VERSION 5.7 ;
  NOWIREEXTENSIONATPIN ON ;
  DIVIDERCHAR "/" ;
  BUSBITCHARS "[]" ;
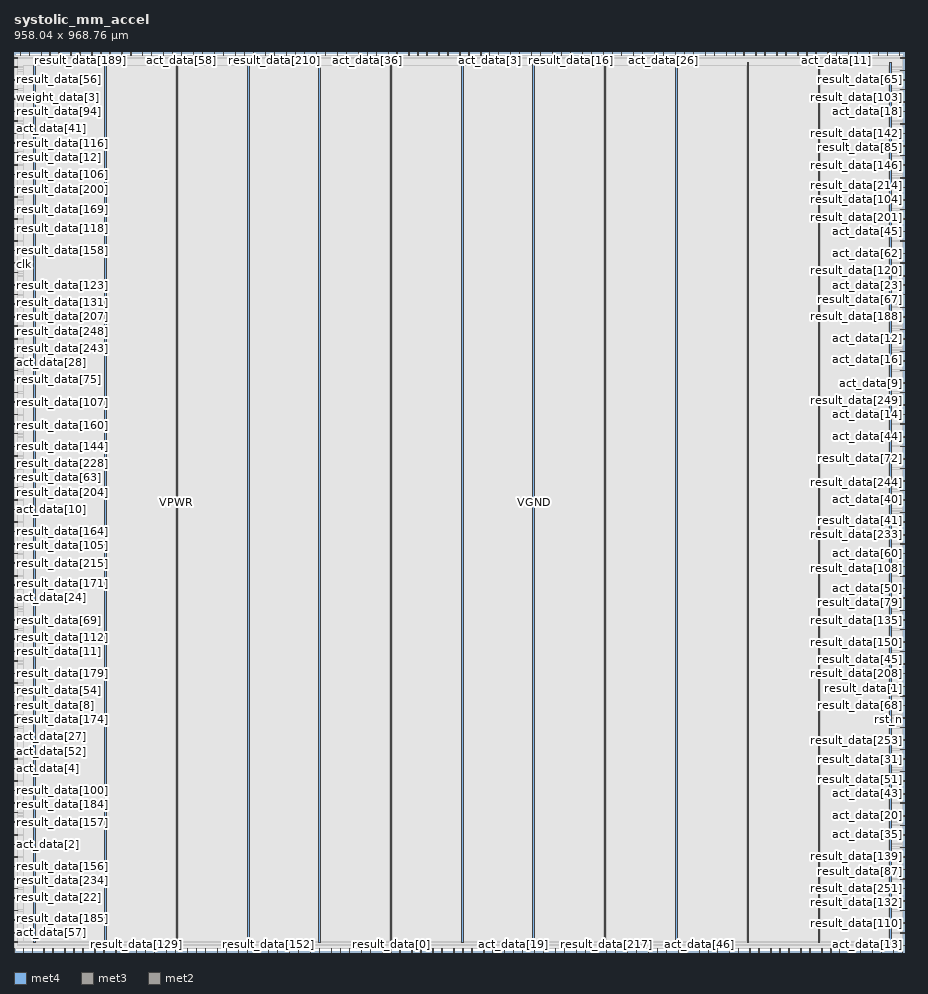
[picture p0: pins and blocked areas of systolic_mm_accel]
MACRO systolic_mm_accel
  CLASS BLOCK ;
  FOREIGN systolic_mm_accel ;
  ORIGIN 0.000 0.000 ;
  SIZE 958.040 BY 968.760 ;
  PIN VGND
    DIRECTION INOUT ;
    USE GROUND ;
    PORT
      LAYER met4 ;
        RECT 97.840 10.640 99.440 957.680 ;
    END
    PORT
      LAYER met4 ;
        RECT 251.440 10.640 253.040 957.680 ;
    END
    PORT
      LAYER met4 ;
        RECT 405.040 10.640 406.640 957.680 ;
    END
    PORT
      LAYER met4 ;
        RECT 558.640 10.640 560.240 957.680 ;
    END
    PORT
      LAYER met4 ;
        RECT 712.240 10.640 713.840 957.680 ;
    END
    PORT
      LAYER met4 ;
        RECT 865.840 10.640 867.440 957.680 ;
    END
  END VGND
  PIN VPWR
    DIRECTION INOUT ;
    USE POWER ;
    PORT
      LAYER met4 ;
        RECT 21.040 10.640 22.640 957.680 ;
    END
    PORT
      LAYER met4 ;
        RECT 174.640 10.640 176.240 957.680 ;
    END
    PORT
      LAYER met4 ;
        RECT 328.240 10.640 329.840 957.680 ;
    END
    PORT
      LAYER met4 ;
        RECT 481.840 10.640 483.440 957.680 ;
    END
    PORT
      LAYER met4 ;
        RECT 635.440 10.640 637.040 957.680 ;
    END
    PORT
      LAYER met4 ;
        RECT 789.040 10.640 790.640 957.680 ;
    END
    PORT
      LAYER met4 ;
        RECT 942.640 10.640 944.240 957.680 ;
    END
  END VPWR
  PIN act_data[0]
    DIRECTION INPUT ;
    USE SIGNAL ;
    ANTENNAGATEAREA 0.647700 ;
    ANTENNADIFFAREA 0.434700 ;
    PORT
      LAYER met3 ;
        RECT 0.000 499.840 4.000 500.440 ;
    END
  END act_data[0]
  PIN act_data[10]
    DIRECTION INPUT ;
    USE SIGNAL ;
    ANTENNAGATEAREA 0.647700 ;
    ANTENNADIFFAREA 0.434700 ;
    PORT
      LAYER met3 ;
        RECT 0.000 476.040 4.000 476.640 ;
    END
  END act_data[10]
  PIN act_data[11]
    DIRECTION INPUT ;
    USE SIGNAL ;
    ANTENNAGATEAREA 0.647700 ;
    ANTENNADIFFAREA 0.434700 ;
    PORT
      LAYER met2 ;
        RECT 885.590 964.760 885.870 968.760 ;
    END
  END act_data[11]
  PIN act_data[12]
    DIRECTION INPUT ;
    USE SIGNAL ;
    ANTENNAGATEAREA 0.593700 ;
    ANTENNADIFFAREA 0.434700 ;
    PORT
      LAYER met3 ;
        RECT 954.040 659.640 958.040 660.240 ;
    END
  END act_data[12]
  PIN act_data[13]
    DIRECTION INPUT ;
    USE SIGNAL ;
    ANTENNAGATEAREA 0.860700 ;
    ANTENNADIFFAREA 0.434700 ;
    PORT
      LAYER met2 ;
        RECT 924.230 0.000 924.510 4.000 ;
    END
  END act_data[13]
  PIN act_data[14]
    DIRECTION INPUT ;
    USE SIGNAL ;
    ANTENNAGATEAREA 0.593700 ;
    ANTENNADIFFAREA 0.434700 ;
    PORT
      LAYER met3 ;
        RECT 954.040 578.040 958.040 578.640 ;
    END
  END act_data[14]
  PIN act_data[15]
    DIRECTION INPUT ;
    USE SIGNAL ;
    ANTENNAGATEAREA 0.682200 ;
    ANTENNADIFFAREA 0.434700 ;
    PORT
      LAYER met2 ;
        RECT 769.670 0.000 769.950 4.000 ;
    END
  END act_data[15]
  PIN act_data[16]
    DIRECTION INPUT ;
    USE SIGNAL ;
    ANTENNAGATEAREA 0.593700 ;
    ANTENNADIFFAREA 0.434700 ;
    PORT
      LAYER met3 ;
        RECT 954.040 646.040 958.040 646.640 ;
    END
  END act_data[16]
  PIN act_data[17]
    DIRECTION INPUT ;
    USE SIGNAL ;
    ANTENNAGATEAREA 0.682200 ;
    ANTENNADIFFAREA 0.434700 ;
    PORT
      LAYER met2 ;
        RECT 296.330 0.000 296.610 4.000 ;
    END
  END act_data[17]
  PIN act_data[18]
    DIRECTION INPUT ;
    USE SIGNAL ;
    ANTENNAGATEAREA 0.647700 ;
    ANTENNADIFFAREA 0.434700 ;
    PORT
      LAYER met3 ;
        RECT 954.040 904.440 958.040 905.040 ;
    END
  END act_data[18]
  PIN act_data[19]
    DIRECTION INPUT ;
    USE SIGNAL ;
    ANTENNAGATEAREA 0.647700 ;
    ANTENNADIFFAREA 0.434700 ;
    PORT
      LAYER met2 ;
        RECT 537.830 0.000 538.110 4.000 ;
    END
  END act_data[19]
  PIN act_data[1]
    DIRECTION INPUT ;
    USE SIGNAL ;
    ANTENNAGATEAREA 0.682200 ;
    ANTENNADIFFAREA 0.434700 ;
    PORT
      LAYER met3 ;
        RECT 0.000 336.640 4.000 337.240 ;
    END
  END act_data[1]
  PIN act_data[20]
    DIRECTION INPUT ;
    USE SIGNAL ;
    ANTENNAGATEAREA 0.682200 ;
    ANTENNADIFFAREA 0.434700 ;
    PORT
      LAYER met3 ;
        RECT 954.040 146.240 958.040 146.840 ;
    END
  END act_data[20]
  PIN act_data[21]
    DIRECTION INPUT ;
    USE SIGNAL ;
    ANTENNAGATEAREA 0.682200 ;
    ANTENNADIFFAREA 0.434700 ;
    PORT
      LAYER met2 ;
        RECT 901.690 0.000 901.970 4.000 ;
    END
  END act_data[21]
  PIN act_data[22]
    DIRECTION INPUT ;
    USE SIGNAL ;
    ANTENNAGATEAREA 0.860700 ;
    ANTENNADIFFAREA 0.434700 ;
    PORT
      LAYER met2 ;
        RECT 16.190 964.760 16.470 968.760 ;
    END
  END act_data[22]
  PIN act_data[23]
    DIRECTION INPUT ;
    USE SIGNAL ;
    ANTENNAGATEAREA 0.647700 ;
    ANTENNADIFFAREA 0.434700 ;
    PORT
      LAYER met3 ;
        RECT 954.040 717.440 958.040 718.040 ;
    END
  END act_data[23]
  PIN act_data[24]
    DIRECTION INPUT ;
    USE SIGNAL ;
    ANTENNAGATEAREA 0.682200 ;
    ANTENNADIFFAREA 0.434700 ;
    PORT
      LAYER met3 ;
        RECT 0.000 380.840 4.000 381.440 ;
    END
  END act_data[24]
  PIN act_data[25]
    DIRECTION INPUT ;
    USE SIGNAL ;
    ANTENNAGATEAREA 0.682200 ;
    ANTENNADIFFAREA 0.434700 ;
    PORT
      LAYER met2 ;
        RECT 257.690 964.760 257.970 968.760 ;
    END
  END act_data[25]
  PIN act_data[26]
    DIRECTION INPUT ;
    USE SIGNAL ;
    ANTENNAGATEAREA 0.593700 ;
    ANTENNADIFFAREA 0.434700 ;
    PORT
      LAYER met2 ;
        RECT 698.830 964.760 699.110 968.760 ;
    END
  END act_data[26]
  PIN act_data[27]
    DIRECTION INPUT ;
    USE SIGNAL ;
    ANTENNAGATEAREA 0.682200 ;
    ANTENNADIFFAREA 0.434700 ;
    PORT
      LAYER met3 ;
        RECT 0.000 231.240 4.000 231.840 ;
    END
  END act_data[27]
  PIN act_data[28]
    DIRECTION INPUT ;
    USE SIGNAL ;
    ANTENNAGATEAREA 0.682200 ;
    ANTENNADIFFAREA 0.434700 ;
    PORT
      LAYER met3 ;
        RECT 0.000 625.640 4.000 626.240 ;
    END
  END act_data[28]
  PIN act_data[29]
    DIRECTION INPUT ;
    USE SIGNAL ;
    ANTENNAGATEAREA 0.647700 ;
    ANTENNADIFFAREA 0.434700 ;
    PORT
      LAYER met2 ;
        RECT 528.170 0.000 528.450 4.000 ;
    END
  END act_data[29]
  PIN act_data[2]
    DIRECTION INPUT ;
    USE SIGNAL ;
    ANTENNAGATEAREA 0.860700 ;
    ANTENNADIFFAREA 0.434700 ;
    PORT
      LAYER met3 ;
        RECT 0.000 115.640 4.000 116.240 ;
    END
  END act_data[2]
  PIN act_data[30]
    DIRECTION INPUT ;
    USE SIGNAL ;
    ANTENNAGATEAREA 0.682200 ;
    ANTENNADIFFAREA 0.434700 ;
    PORT
      LAYER met2 ;
        RECT 264.130 0.000 264.410 4.000 ;
    END
  END act_data[30]
  PIN act_data[31]
    DIRECTION INPUT ;
    USE SIGNAL ;
    ANTENNAGATEAREA 0.682200 ;
    ANTENNADIFFAREA 0.434700 ;
    PORT
      LAYER met2 ;
        RECT 193.290 964.760 193.570 968.760 ;
    END
  END act_data[31]
  PIN act_data[32]
    DIRECTION INPUT ;
    USE SIGNAL ;
    ANTENNAGATEAREA 0.593700 ;
    ANTENNADIFFAREA 0.434700 ;
    PORT
      LAYER met2 ;
        RECT 869.490 0.000 869.770 4.000 ;
    END
  END act_data[32]
  PIN act_data[33]
    DIRECTION INPUT ;
    USE SIGNAL ;
    ANTENNAGATEAREA 0.682200 ;
    ANTENNADIFFAREA 0.434700 ;
    PORT
      LAYER met3 ;
        RECT 0.000 278.840 4.000 279.440 ;
    END
  END act_data[33]
  PIN act_data[34]
    DIRECTION INPUT ;
    USE SIGNAL ;
    ANTENNAGATEAREA 0.682200 ;
    ANTENNADIFFAREA 0.434700 ;
    PORT
      LAYER met3 ;
        RECT 0.000 639.240 4.000 639.840 ;
    END
  END act_data[34]
  PIN act_data[35]
    DIRECTION INPUT ;
    USE SIGNAL ;
    ANTENNAGATEAREA 0.647700 ;
    ANTENNADIFFAREA 0.434700 ;
    PORT
      LAYER met3 ;
        RECT 954.040 125.840 958.040 126.440 ;
    END
  END act_data[35]
  PIN act_data[36]
    DIRECTION INPUT ;
    USE SIGNAL ;
    ANTENNAGATEAREA 0.682200 ;
    ANTENNADIFFAREA 0.434700 ;
    PORT
      LAYER met2 ;
        RECT 380.050 964.760 380.330 968.760 ;
    END
  END act_data[36]
  PIN act_data[37]
    DIRECTION INPUT ;
    USE SIGNAL ;
    ANTENNAGATEAREA 0.860700 ;
    ANTENNADIFFAREA 0.434700 ;
    PORT
      LAYER met2 ;
        RECT 215.830 964.760 216.110 968.760 ;
    END
  END act_data[37]
  PIN act_data[38]
    DIRECTION INPUT ;
    USE SIGNAL ;
    ANTENNAGATEAREA 0.647700 ;
    ANTENNADIFFAREA 0.434700 ;
    PORT
      LAYER met3 ;
        RECT 954.040 112.240 958.040 112.840 ;
    END
  END act_data[38]
  PIN act_data[39]
    DIRECTION INPUT ;
    USE SIGNAL ;
    ANTENNAGATEAREA 0.682200 ;
    ANTENNADIFFAREA 0.434700 ;
    PORT
      LAYER met2 ;
        RECT 334.970 964.760 335.250 968.760 ;
    END
  END act_data[39]
  PIN act_data[3]
    DIRECTION INPUT ;
    USE SIGNAL ;
    ANTENNAGATEAREA 0.593700 ;
    ANTENNADIFFAREA 0.434700 ;
    PORT
      LAYER met2 ;
        RECT 512.070 964.760 512.350 968.760 ;
    END
  END act_data[3]
  PIN act_data[40]
    DIRECTION INPUT ;
    USE SIGNAL ;
    ANTENNAGATEAREA 0.631200 ;
    ANTENNADIFFAREA 0.434700 ;
    PORT
      LAYER met3 ;
        RECT 954.040 486.240 958.040 486.840 ;
    END
  END act_data[40]
  PIN act_data[41]
    DIRECTION INPUT ;
    USE SIGNAL ;
    ANTENNAGATEAREA 0.860700 ;
    ANTENNADIFFAREA 0.434700 ;
    PORT
      LAYER met3 ;
        RECT 0.000 894.240 4.000 894.840 ;
    END
  END act_data[41]
  PIN act_data[42]
    DIRECTION INPUT ;
    USE SIGNAL ;
    ANTENNAGATEAREA 0.860700 ;
    ANTENNADIFFAREA 0.434700 ;
    PORT
      LAYER met2 ;
        RECT 54.830 0.000 55.110 4.000 ;
    END
  END act_data[42]
  PIN act_data[43]
    DIRECTION INPUT ;
    USE SIGNAL ;
    ANTENNAGATEAREA 0.560700 ;
    ANTENNADIFFAREA 0.434700 ;
    PORT
      LAYER met3 ;
        RECT 954.040 170.040 958.040 170.640 ;
    END
  END act_data[43]
  PIN act_data[44]
    DIRECTION INPUT ;
    USE SIGNAL ;
    ANTENNAGATEAREA 0.631200 ;
    ANTENNADIFFAREA 0.434700 ;
    PORT
      LAYER met3 ;
        RECT 954.040 554.240 958.040 554.840 ;
    END
  END act_data[44]
  PIN act_data[45]
    DIRECTION INPUT ;
    USE SIGNAL ;
    ANTENNAGATEAREA 0.647700 ;
    ANTENNADIFFAREA 0.434700 ;
    PORT
      LAYER met3 ;
        RECT 954.040 775.240 958.040 775.840 ;
    END
  END act_data[45]
  PIN act_data[46]
    DIRECTION INPUT ;
    USE SIGNAL ;
    ANTENNAGATEAREA 0.593700 ;
    ANTENNADIFFAREA 0.434700 ;
    PORT
      LAYER met2 ;
        RECT 737.470 0.000 737.750 4.000 ;
    END
  END act_data[46]
  PIN act_data[47]
    DIRECTION INPUT ;
    USE SIGNAL ;
    ANTENNAGATEAREA 0.647700 ;
    ANTENNADIFFAREA 0.434700 ;
    PORT
      LAYER met2 ;
        RECT 660.190 0.000 660.470 4.000 ;
    END
  END act_data[47]
  PIN act_data[48]
    DIRECTION INPUT ;
    USE SIGNAL ;
    ANTENNAGATEAREA 0.631200 ;
    ANTENNADIFFAREA 0.434700 ;
    PORT
      LAYER met2 ;
        RECT 875.930 964.760 876.210 968.760 ;
    END
  END act_data[48]
  PIN act_data[49]
    DIRECTION INPUT ;
    USE SIGNAL ;
    ANTENNAGATEAREA 0.560700 ;
    ANTENNADIFFAREA 0.434700 ;
    PORT
      LAYER met3 ;
        RECT 954.040 251.640 958.040 252.240 ;
    END
  END act_data[49]
  PIN act_data[4]
    DIRECTION INPUT ;
    USE SIGNAL ;
    ANTENNAGATEAREA 0.929700 ;
    ANTENNADIFFAREA 0.434700 ;
    PORT
      LAYER met3 ;
        RECT 0.000 197.240 4.000 197.840 ;
    END
  END act_data[4]
  PIN act_data[50]
    DIRECTION INPUT ;
    USE SIGNAL ;
    ANTENNAGATEAREA 0.631200 ;
    ANTENNADIFFAREA 0.434700 ;
    PORT
      LAYER met3 ;
        RECT 954.040 391.040 958.040 391.640 ;
    END
  END act_data[50]
  PIN act_data[51]
    DIRECTION INPUT ;
    USE SIGNAL ;
    ANTENNAGATEAREA 0.631200 ;
    ANTENNADIFFAREA 0.434700 ;
    PORT
      LAYER met2 ;
        RECT 930.670 964.760 930.950 968.760 ;
    END
  END act_data[51]
  PIN act_data[52]
    DIRECTION INPUT ;
    USE SIGNAL ;
    ANTENNAGATEAREA 0.860700 ;
    ANTENNADIFFAREA 0.434700 ;
    PORT
      LAYER met3 ;
        RECT 0.000 207.440 4.000 208.040 ;
    END
  END act_data[52]
  PIN act_data[53]
    DIRECTION INPUT ;
    USE SIGNAL ;
    ANTENNAGATEAREA 0.593700 ;
    ANTENNADIFFAREA 0.434700 ;
    PORT
      LAYER met2 ;
        RECT 544.270 964.760 544.550 968.760 ;
    END
  END act_data[53]
  PIN act_data[54]
    DIRECTION INPUT ;
    USE SIGNAL ;
    ANTENNAGATEAREA 0.631200 ;
    ANTENNADIFFAREA 0.434700 ;
    PORT
      LAYER met2 ;
        RECT 853.390 964.760 853.670 968.760 ;
    END
  END act_data[54]
  PIN act_data[55]
    DIRECTION INPUT ;
    USE SIGNAL ;
    ANTENNAGATEAREA 0.560700 ;
    ANTENNADIFFAREA 0.434700 ;
    PORT
      LAYER met2 ;
        RECT 676.290 964.760 676.570 968.760 ;
    END
  END act_data[55]
  PIN act_data[56]
    DIRECTION INPUT ;
    USE SIGNAL ;
    ANTENNAGATEAREA 0.647700 ;
    ANTENNADIFFAREA 0.434700 ;
    PORT
      LAYER met2 ;
        RECT 138.550 964.760 138.830 968.760 ;
    END
  END act_data[56]
  PIN act_data[57]
    DIRECTION INPUT ;
    USE SIGNAL ;
    ANTENNAGATEAREA 0.929700 ;
    ANTENNADIFFAREA 0.434700 ;
    PORT
      LAYER met3 ;
        RECT 0.000 20.440 4.000 21.040 ;
    END
  END act_data[57]
  PIN act_data[58]
    DIRECTION INPUT ;
    USE SIGNAL ;
    ANTENNAGATEAREA 0.647700 ;
    ANTENNADIFFAREA 0.434700 ;
    PORT
      LAYER met2 ;
        RECT 180.410 964.760 180.690 968.760 ;
    END
  END act_data[58]
  PIN act_data[59]
    DIRECTION INPUT ;
    USE SIGNAL ;
    ANTENNAGATEAREA 0.647700 ;
    ANTENNADIFFAREA 0.434700 ;
    PORT
      LAYER met2 ;
        RECT 93.470 964.760 93.750 968.760 ;
    END
  END act_data[59]
  PIN act_data[5]
    DIRECTION INPUT ;
    USE SIGNAL ;
    ANTENNAGATEAREA 0.647700 ;
    ANTENNADIFFAREA 0.434700 ;
    PORT
      LAYER met2 ;
        RECT 653.750 964.760 654.030 968.760 ;
    END
  END act_data[5]
  PIN act_data[60]
    DIRECTION INPUT ;
    USE SIGNAL ;
    ANTENNAGATEAREA 0.631200 ;
    ANTENNADIFFAREA 0.434700 ;
    PORT
      LAYER met3 ;
        RECT 954.040 428.440 958.040 429.040 ;
    END
  END act_data[60]
  PIN act_data[61]
    DIRECTION INPUT ;
    USE SIGNAL ;
    ANTENNAGATEAREA 0.647700 ;
    ANTENNADIFFAREA 0.434700 ;
    PORT
      LAYER met2 ;
        RECT 438.010 0.000 438.290 4.000 ;
    END
  END act_data[61]
  PIN act_data[62]
    DIRECTION INPUT ;
    USE SIGNAL ;
    ANTENNAGATEAREA 0.631200 ;
    ANTENNADIFFAREA 0.434700 ;
    PORT
      LAYER met3 ;
        RECT 954.040 751.440 958.040 752.040 ;
    END
  END act_data[62]
  PIN act_data[63]
    DIRECTION INPUT ;
    USE SIGNAL ;
    ANTENNAGATEAREA 0.860700 ;
    ANTENNADIFFAREA 0.434700 ;
    PORT
      LAYER met2 ;
        RECT 151.430 0.000 151.710 4.000 ;
    END
  END act_data[63]
  PIN act_data[6]
    DIRECTION INPUT ;
    USE SIGNAL ;
    ANTENNAGATEAREA 0.647700 ;
    ANTENNADIFFAREA 0.434700 ;
    PORT
      LAYER met2 ;
        RECT 898.470 964.760 898.750 968.760 ;
    END
  END act_data[6]
  PIN act_data[7]
    DIRECTION INPUT ;
    USE SIGNAL ;
    ANTENNAGATEAREA 1.177200 ;
    ANTENNADIFFAREA 0.434700 ;
    PORT
      LAYER met3 ;
        RECT 0.000 10.240 4.000 10.840 ;
    END
  END act_data[7]
  PIN act_data[8]
    DIRECTION INPUT ;
    USE SIGNAL ;
    ANTENNAGATEAREA 0.647700 ;
    ANTENNADIFFAREA 0.434700 ;
    PORT
      LAYER met2 ;
        RECT 557.150 964.760 557.430 968.760 ;
    END
  END act_data[8]
  PIN act_data[9]
    DIRECTION INPUT ;
    USE SIGNAL ;
    ANTENNAGATEAREA 0.593700 ;
    ANTENNADIFFAREA 0.434700 ;
    PORT
      LAYER met3 ;
        RECT 954.040 612.040 958.040 612.640 ;
    END
  END act_data[9]
  PIN act_ready
    DIRECTION OUTPUT TRISTATE ;
    USE SIGNAL ;
    ANTENNADIFFAREA 0.795200 ;
    PORT
      LAYER met2 ;
        RECT 225.490 964.760 225.770 968.760 ;
    END
  END act_ready
  PIN act_valid
    DIRECTION INPUT ;
    USE SIGNAL ;
    ANTENNAGATEAREA 0.647700 ;
    ANTENNADIFFAREA 0.434700 ;
    PORT
      LAYER met2 ;
        RECT 621.550 964.760 621.830 968.760 ;
    END
  END act_valid
  PIN clk
    DIRECTION INPUT ;
    USE SIGNAL ;
    ANTENNAGATEAREA 1.286700 ;
    ANTENNADIFFAREA 0.434700 ;
    PORT
      LAYER met3 ;
        RECT 0.000 731.040 4.000 731.640 ;
    END
  END clk
  PIN result_data[0]
    DIRECTION OUTPUT TRISTATE ;
    USE SIGNAL ;
    ANTENNADIFFAREA 0.795200 ;
    PORT
      LAYER met2 ;
        RECT 405.810 0.000 406.090 4.000 ;
    END
  END result_data[0]
  PIN result_data[100]
    DIRECTION OUTPUT TRISTATE ;
    USE SIGNAL ;
    ANTENNADIFFAREA 0.795200 ;
    PORT
      LAYER met3 ;
        RECT 0.000 173.440 4.000 174.040 ;
    END
  END result_data[100]
  PIN result_data[101]
    DIRECTION OUTPUT TRISTATE ;
    USE SIGNAL ;
    ANTENNADIFFAREA 0.445500 ;
    PORT
      LAYER met3 ;
        RECT 954.040 635.840 958.040 636.440 ;
    END
  END result_data[101]
  PIN result_data[102]
    DIRECTION OUTPUT TRISTATE ;
    USE SIGNAL ;
    ANTENNADIFFAREA 0.795200 ;
    PORT
      LAYER met2 ;
        RECT 241.590 0.000 241.870 4.000 ;
    END
  END result_data[102]
  PIN result_data[103]
    DIRECTION OUTPUT TRISTATE ;
    USE SIGNAL ;
    ANTENNADIFFAREA 0.445500 ;
    PORT
      LAYER met3 ;
        RECT 954.040 928.240 958.040 928.840 ;
    END
  END result_data[103]
  PIN result_data[104]
    DIRECTION OUTPUT TRISTATE ;
    USE SIGNAL ;
    ANTENNADIFFAREA 0.445500 ;
    PORT
      LAYER met3 ;
        RECT 954.040 809.240 958.040 809.840 ;
    END
  END result_data[104]
  PIN result_data[105]
    DIRECTION OUTPUT TRISTATE ;
    USE SIGNAL ;
    ANTENNADIFFAREA 0.795200 ;
    PORT
      LAYER met3 ;
        RECT 0.000 428.440 4.000 429.040 ;
    END
  END result_data[105]
  PIN result_data[106]
    DIRECTION OUTPUT TRISTATE ;
    USE SIGNAL ;
    ANTENNADIFFAREA 0.795200 ;
    PORT
      LAYER met3 ;
        RECT 0.000 836.440 4.000 837.040 ;
    END
  END result_data[106]
  PIN result_data[107]
    DIRECTION OUTPUT TRISTATE ;
    USE SIGNAL ;
    ANTENNADIFFAREA 0.795200 ;
    PORT
      LAYER met3 ;
        RECT 0.000 591.640 4.000 592.240 ;
    END
  END result_data[107]
  PIN result_data[108]
    DIRECTION OUTPUT TRISTATE ;
    USE SIGNAL ;
    ANTENNADIFFAREA 0.445500 ;
    PORT
      LAYER met3 ;
        RECT 954.040 404.640 958.040 405.240 ;
    END
  END result_data[108]
  PIN result_data[109]
    DIRECTION OUTPUT TRISTATE ;
    USE SIGNAL ;
    ANTENNADIFFAREA 0.795200 ;
    PORT
      LAYER met2 ;
        RECT 592.570 0.000 592.850 4.000 ;
    END
  END result_data[109]
  PIN result_data[10]
    DIRECTION OUTPUT TRISTATE ;
    USE SIGNAL ;
    ANTENNADIFFAREA 0.795200 ;
    PORT
      LAYER met2 ;
        RECT 186.850 0.000 187.130 4.000 ;
    END
  END result_data[10]
  PIN result_data[110]
    DIRECTION OUTPUT TRISTATE ;
    USE SIGNAL ;
    ANTENNADIFFAREA 0.445500 ;
    PORT
      LAYER met3 ;
        RECT 954.040 30.640 958.040 31.240 ;
    END
  END result_data[110]
  PIN result_data[111]
    DIRECTION OUTPUT TRISTATE ;
    USE SIGNAL ;
    ANTENNADIFFAREA 0.445500 ;
    PORT
      LAYER met3 ;
        RECT 954.040 159.840 958.040 160.440 ;
    END
  END result_data[111]
  PIN result_data[112]
    DIRECTION OUTPUT TRISTATE ;
    USE SIGNAL ;
    ANTENNADIFFAREA 0.795200 ;
    PORT
      LAYER met3 ;
        RECT 0.000 346.840 4.000 347.440 ;
    END
  END result_data[112]
  PIN result_data[113]
    DIRECTION OUTPUT TRISTATE ;
    USE SIGNAL ;
    ANTENNADIFFAREA 0.795200 ;
    PORT
      LAYER met2 ;
        RECT 460.550 0.000 460.830 4.000 ;
    END
  END result_data[113]
  PIN result_data[114]
    DIRECTION OUTPUT TRISTATE ;
    USE SIGNAL ;
    ANTENNADIFFAREA 0.795200 ;
    PORT
      LAYER met2 ;
        RECT 785.770 964.760 786.050 968.760 ;
    END
  END result_data[114]
  PIN result_data[115]
    DIRECTION OUTPUT TRISTATE ;
    USE SIGNAL ;
    ANTENNADIFFAREA 0.795200 ;
    PORT
      LAYER met3 ;
        RECT 954.040 20.440 958.040 21.040 ;
    END
  END result_data[115]
  PIN result_data[116]
    DIRECTION OUTPUT TRISTATE ;
    USE SIGNAL ;
    ANTENNADIFFAREA 0.795200 ;
    PORT
      LAYER met3 ;
        RECT 0.000 870.440 4.000 871.040 ;
    END
  END result_data[116]
  PIN result_data[117]
    DIRECTION OUTPUT TRISTATE ;
    USE SIGNAL ;
    ANTENNADIFFAREA 0.795200 ;
    PORT
      LAYER met2 ;
        RECT 753.570 964.760 753.850 968.760 ;
    END
  END result_data[117]
  PIN result_data[118]
    DIRECTION OUTPUT TRISTATE ;
    USE SIGNAL ;
    ANTENNADIFFAREA 0.795200 ;
    PORT
      LAYER met3 ;
        RECT 0.000 778.640 4.000 779.240 ;
    END
  END result_data[118]
  PIN result_data[119]
    DIRECTION OUTPUT TRISTATE ;
    USE SIGNAL ;
    ANTENNADIFFAREA 0.795200 ;
    PORT
      LAYER met2 ;
        RECT 953.210 964.760 953.490 968.760 ;
    END
  END result_data[119]
  PIN result_data[11]
    DIRECTION OUTPUT TRISTATE ;
    USE SIGNAL ;
    ANTENNADIFFAREA 0.795200 ;
    PORT
      LAYER met3 ;
        RECT 0.000 323.040 4.000 323.640 ;
    END
  END result_data[11]
  PIN result_data[120]
    DIRECTION OUTPUT TRISTATE ;
    USE SIGNAL ;
    ANTENNADIFFAREA 0.445500 ;
    PORT
      LAYER met3 ;
        RECT 954.040 741.240 958.040 741.840 ;
    END
  END result_data[120]
  PIN result_data[121]
    DIRECTION OUTPUT TRISTATE ;
    USE SIGNAL ;
    ANTENNADIFFAREA 0.795200 ;
    PORT
      LAYER met2 ;
        RECT 302.770 964.760 303.050 968.760 ;
    END
  END result_data[121]
  PIN result_data[122]
    DIRECTION OUTPUT TRISTATE ;
    USE SIGNAL ;
    ANTENNADIFFAREA 0.795200 ;
    PORT
      LAYER met2 ;
        RECT 830.850 964.760 831.130 968.760 ;
    END
  END result_data[122]
  PIN result_data[123]
    DIRECTION OUTPUT TRISTATE ;
    USE SIGNAL ;
    ANTENNADIFFAREA 0.795200 ;
    PORT
      LAYER met3 ;
        RECT 0.000 717.440 4.000 718.040 ;
    END
  END result_data[123]
  PIN result_data[124]
    DIRECTION OUTPUT TRISTATE ;
    USE SIGNAL ;
    ANTENNADIFFAREA 0.795200 ;
    PORT
      LAYER met2 ;
        RECT 370.390 964.760 370.670 968.760 ;
    END
  END result_data[124]
  PIN result_data[125]
    DIRECTION OUTPUT TRISTATE ;
    USE SIGNAL ;
    ANTENNADIFFAREA 0.795200 ;
    PORT
      LAYER met2 ;
        RECT 38.730 964.760 39.010 968.760 ;
    END
  END result_data[125]
  PIN result_data[126]
    DIRECTION OUTPUT TRISTATE ;
    USE SIGNAL ;
    ANTENNADIFFAREA 0.795200 ;
    PORT
      LAYER met2 ;
        RECT 328.530 0.000 328.810 4.000 ;
    END
  END result_data[126]
  PIN result_data[127]
    DIRECTION OUTPUT TRISTATE ;
    USE SIGNAL ;
    ANTENNADIFFAREA 0.795200 ;
    PORT
      LAYER met2 ;
        RECT 579.690 964.760 579.970 968.760 ;
    END
  END result_data[127]
  PIN result_data[128]
    DIRECTION OUTPUT TRISTATE ;
    USE SIGNAL ;
    ANTENNADIFFAREA 0.445500 ;
    PORT
      LAYER met2 ;
        RECT 161.090 964.760 161.370 968.760 ;
    END
  END result_data[128]
  PIN result_data[129]
    DIRECTION OUTPUT TRISTATE ;
    USE SIGNAL ;
    ANTENNADIFFAREA 0.795200 ;
    PORT
      LAYER met2 ;
        RECT 132.110 0.000 132.390 4.000 ;
    END
  END result_data[129]
  PIN result_data[12]
    DIRECTION OUTPUT TRISTATE ;
    USE SIGNAL ;
    ANTENNADIFFAREA 0.795200 ;
    PORT
      LAYER met3 ;
        RECT 0.000 846.640 4.000 847.240 ;
    END
  END result_data[12]
  PIN result_data[130]
    DIRECTION OUTPUT TRISTATE ;
    USE SIGNAL ;
    ANTENNADIFFAREA 0.795200 ;
    PORT
      LAYER met3 ;
        RECT 0.000 952.040 4.000 952.640 ;
    END
  END result_data[130]
  PIN result_data[131]
    DIRECTION OUTPUT TRISTATE ;
    USE SIGNAL ;
    ANTENNADIFFAREA 0.795200 ;
    PORT
      LAYER met3 ;
        RECT 0.000 707.240 4.000 707.840 ;
    END
  END result_data[131]
  PIN result_data[132]
    DIRECTION OUTPUT TRISTATE ;
    USE SIGNAL ;
    ANTENNADIFFAREA 0.445500 ;
    PORT
      LAYER met3 ;
        RECT 954.040 44.240 958.040 44.840 ;
    END
  END result_data[132]
  PIN result_data[133]
    DIRECTION OUTPUT TRISTATE ;
    USE SIGNAL ;
    ANTENNADIFFAREA 0.445500 ;
    PORT
      LAYER met2 ;
        RECT 148.210 964.760 148.490 968.760 ;
    END
  END result_data[133]
  PIN result_data[134]
    DIRECTION OUTPUT TRISTATE ;
    USE SIGNAL ;
    ANTENNADIFFAREA 0.445500 ;
    PORT
      LAYER met2 ;
        RECT 347.850 964.760 348.130 968.760 ;
    END
  END result_data[134]
  PIN result_data[135]
    DIRECTION OUTPUT TRISTATE ;
    USE SIGNAL ;
    ANTENNADIFFAREA 0.445500 ;
    PORT
      LAYER met3 ;
        RECT 954.040 357.040 958.040 357.640 ;
    END
  END result_data[135]
  PIN result_data[136]
    DIRECTION OUTPUT TRISTATE ;
    USE SIGNAL ;
    ANTENNADIFFAREA 0.795200 ;
    PORT
      LAYER met2 ;
        RECT 251.250 0.000 251.530 4.000 ;
    END
  END result_data[136]
  PIN result_data[137]
    DIRECTION OUTPUT TRISTATE ;
    USE SIGNAL ;
    ANTENNADIFFAREA 0.795200 ;
    PORT
      LAYER met2 ;
        RECT 956.430 0.000 956.710 4.000 ;
    END
  END result_data[137]
  PIN result_data[138]
    DIRECTION OUTPUT TRISTATE ;
    USE SIGNAL ;
    ANTENNADIFFAREA 0.795200 ;
    PORT
      LAYER met2 ;
        RECT 547.490 0.000 547.770 4.000 ;
    END
  END result_data[138]
  PIN result_data[139]
    DIRECTION OUTPUT TRISTATE ;
    USE SIGNAL ;
    ANTENNADIFFAREA 0.795200 ;
    PORT
      LAYER met3 ;
        RECT 954.040 102.040 958.040 102.640 ;
    END
  END result_data[139]
  PIN result_data[13]
    DIRECTION OUTPUT TRISTATE ;
    USE SIGNAL ;
    ANTENNADIFFAREA 0.795200 ;
    PORT
      LAYER met2 ;
        RECT 921.010 964.760 921.290 968.760 ;
    END
  END result_data[13]
  PIN result_data[140]
    DIRECTION OUTPUT TRISTATE ;
    USE SIGNAL ;
    ANTENNADIFFAREA 0.795200 ;
    PORT
      LAYER met2 ;
        RECT 779.330 0.000 779.610 4.000 ;
    END
  END result_data[140]
  PIN result_data[141]
    DIRECTION OUTPUT TRISTATE ;
    USE SIGNAL ;
    ANTENNADIFFAREA 0.795200 ;
    PORT
      LAYER met2 ;
        RECT 360.730 0.000 361.010 4.000 ;
    END
  END result_data[141]
  PIN result_data[142]
    DIRECTION OUTPUT TRISTATE ;
    USE SIGNAL ;
    ANTENNADIFFAREA 0.445500 ;
    PORT
      LAYER met3 ;
        RECT 954.040 880.640 958.040 881.240 ;
    END
  END result_data[142]
  PIN result_data[143]
    DIRECTION OUTPUT TRISTATE ;
    USE SIGNAL ;
    ANTENNADIFFAREA 0.795200 ;
    PORT
      LAYER met2 ;
        RECT 238.370 964.760 238.650 968.760 ;
    END
  END result_data[143]
  PIN result_data[144]
    DIRECTION OUTPUT TRISTATE ;
    USE SIGNAL ;
    ANTENNADIFFAREA 0.795200 ;
    PORT
      LAYER met3 ;
        RECT 0.000 544.040 4.000 544.640 ;
    END
  END result_data[144]
  PIN result_data[145]
    DIRECTION OUTPUT TRISTATE ;
    USE SIGNAL ;
    ANTENNADIFFAREA 0.445500 ;
    PORT
      LAYER met3 ;
        RECT 954.040 183.640 958.040 184.240 ;
    END
  END result_data[145]
  PIN result_data[146]
    DIRECTION OUTPUT TRISTATE ;
    USE SIGNAL ;
    ANTENNADIFFAREA 0.445500 ;
    PORT
      LAYER met3 ;
        RECT 954.040 846.640 958.040 847.240 ;
    END
  END result_data[146]
  PIN result_data[147]
    DIRECTION OUTPUT TRISTATE ;
    USE SIGNAL ;
    ANTENNADIFFAREA 0.795200 ;
    PORT
      LAYER met2 ;
        RECT 911.350 0.000 911.630 4.000 ;
    END
  END result_data[147]
  PIN result_data[148]
    DIRECTION OUTPUT TRISTATE ;
    USE SIGNAL ;
    ANTENNADIFFAREA 0.795200 ;
    PORT
      LAYER met2 ;
        RECT 383.270 0.000 383.550 4.000 ;
    END
  END result_data[148]
  PIN result_data[149]
    DIRECTION OUTPUT TRISTATE ;
    USE SIGNAL ;
    ANTENNADIFFAREA 0.795200 ;
    PORT
      LAYER met2 ;
        RECT 801.870 0.000 802.150 4.000 ;
    END
  END result_data[149]
  PIN result_data[14]
    DIRECTION OUTPUT TRISTATE ;
    USE SIGNAL ;
    ANTENNADIFFAREA 0.795200 ;
    PORT
      LAYER met2 ;
        RECT 96.690 0.000 96.970 4.000 ;
    END
  END result_data[14]
  PIN result_data[150]
    DIRECTION OUTPUT TRISTATE ;
    USE SIGNAL ;
    ANTENNADIFFAREA 0.445500 ;
    PORT
      LAYER met3 ;
        RECT 954.040 333.240 958.040 333.840 ;
    END
  END result_data[150]
  PIN result_data[151]
    DIRECTION OUTPUT TRISTATE ;
    USE SIGNAL ;
    ANTENNADIFFAREA 0.445500 ;
    PORT
      LAYER met3 ;
        RECT 954.040 625.640 958.040 626.240 ;
    END
  END result_data[151]
  PIN result_data[152]
    DIRECTION OUTPUT TRISTATE ;
    USE SIGNAL ;
    ANTENNADIFFAREA 0.795200 ;
    PORT
      LAYER met2 ;
        RECT 273.790 0.000 274.070 4.000 ;
    END
  END result_data[152]
  PIN result_data[153]
    DIRECTION OUTPUT TRISTATE ;
    USE SIGNAL ;
    ANTENNADIFFAREA 0.795200 ;
    PORT
      LAYER met3 ;
        RECT 954.040 88.440 958.040 89.040 ;
    END
  END result_data[153]
  PIN result_data[154]
    DIRECTION OUTPUT TRISTATE ;
    USE SIGNAL ;
    ANTENNADIFFAREA 0.795200 ;
    PORT
      LAYER met2 ;
        RECT 756.790 0.000 757.070 4.000 ;
    END
  END result_data[154]
  PIN result_data[155]
    DIRECTION OUTPUT TRISTATE ;
    USE SIGNAL ;
    ANTENNADIFFAREA 0.795200 ;
    PORT
      LAYER met2 ;
        RECT 570.030 0.000 570.310 4.000 ;
    END
  END result_data[155]
  PIN result_data[156]
    DIRECTION OUTPUT TRISTATE ;
    USE SIGNAL ;
    ANTENNADIFFAREA 0.795200 ;
    PORT
      LAYER met3 ;
        RECT 0.000 91.840 4.000 92.440 ;
    END
  END result_data[156]
  PIN result_data[157]
    DIRECTION OUTPUT TRISTATE ;
    USE SIGNAL ;
    ANTENNADIFFAREA 0.795200 ;
    PORT
      LAYER met3 ;
        RECT 0.000 139.440 4.000 140.040 ;
    END
  END result_data[157]
  PIN result_data[158]
    DIRECTION OUTPUT TRISTATE ;
    USE SIGNAL ;
    ANTENNADIFFAREA 0.795200 ;
    PORT
      LAYER met3 ;
        RECT 0.000 754.840 4.000 755.440 ;
    END
  END result_data[158]
  PIN result_data[159]
    DIRECTION OUTPUT TRISTATE ;
    USE SIGNAL ;
    ANTENNADIFFAREA 0.445500 ;
    PORT
      LAYER met3 ;
        RECT 954.040 380.840 958.040 381.440 ;
    END
  END result_data[159]
  PIN result_data[15]
    DIRECTION OUTPUT TRISTATE ;
    USE SIGNAL ;
    ANTENNADIFFAREA 0.795200 ;
    PORT
      LAYER met2 ;
        RECT 248.030 964.760 248.310 968.760 ;
    END
  END result_data[15]
  PIN result_data[160]
    DIRECTION OUTPUT TRISTATE ;
    USE SIGNAL ;
    ANTENNADIFFAREA 0.795200 ;
    PORT
      LAYER met3 ;
        RECT 0.000 557.640 4.000 558.240 ;
    END
  END result_data[160]
  PIN result_data[161]
    DIRECTION OUTPUT TRISTATE ;
    USE SIGNAL ;
    ANTENNADIFFAREA 0.445500 ;
    PORT
      LAYER met3 ;
        RECT 954.040 867.040 958.040 867.640 ;
    END
  END result_data[161]
  PIN result_data[162]
    DIRECTION OUTPUT TRISTATE ;
    USE SIGNAL ;
    ANTENNADIFFAREA 0.795200 ;
    PORT
      LAYER met2 ;
        RECT 473.430 0.000 473.710 4.000 ;
    END
  END result_data[162]
  PIN result_data[163]
    DIRECTION OUTPUT TRISTATE ;
    USE SIGNAL ;
    ANTENNADIFFAREA 0.795200 ;
    PORT
      LAYER met2 ;
        RECT 61.270 964.760 61.550 968.760 ;
    END
  END result_data[163]
  PIN result_data[164]
    DIRECTION OUTPUT TRISTATE ;
    USE SIGNAL ;
    ANTENNADIFFAREA 0.795200 ;
    PORT
      LAYER met3 ;
        RECT 0.000 452.240 4.000 452.840 ;
    END
  END result_data[164]
  PIN result_data[165]
    DIRECTION OUTPUT TRISTATE ;
    USE SIGNAL ;
    ANTENNADIFFAREA 0.795200 ;
    PORT
      LAYER met3 ;
        RECT 0.000 741.240 4.000 741.840 ;
    END
  END result_data[165]
  PIN result_data[166]
    DIRECTION OUTPUT TRISTATE ;
    USE SIGNAL ;
    ANTENNADIFFAREA 0.795200 ;
    PORT
      LAYER met3 ;
        RECT 0.000 860.240 4.000 860.840 ;
    END
  END result_data[166]
  PIN result_data[167]
    DIRECTION OUTPUT TRISTATE ;
    USE SIGNAL ;
    ANTENNADIFFAREA 0.795200 ;
    PORT
      LAYER met2 ;
        RECT 305.990 0.000 306.270 4.000 ;
    END
  END result_data[167]
  PIN result_data[168]
    DIRECTION OUTPUT TRISTATE ;
    USE SIGNAL ;
    ANTENNADIFFAREA 0.795200 ;
    PORT
      LAYER met2 ;
        RECT 589.350 964.760 589.630 968.760 ;
    END
  END result_data[168]
  PIN result_data[169]
    DIRECTION OUTPUT TRISTATE ;
    USE SIGNAL ;
    ANTENNADIFFAREA 0.795200 ;
    PORT
      LAYER met3 ;
        RECT 0.000 799.040 4.000 799.640 ;
    END
  END result_data[169]
  PIN result_data[16]
    DIRECTION OUTPUT TRISTATE ;
    USE SIGNAL ;
    ANTENNADIFFAREA 0.795200 ;
    PORT
      LAYER met2 ;
        RECT 599.010 964.760 599.290 968.760 ;
    END
  END result_data[16]
  PIN result_data[170]
    DIRECTION OUTPUT TRISTATE ;
    USE SIGNAL ;
    ANTENNADIFFAREA 0.795200 ;
    PORT
      LAYER met2 ;
        RECT 908.130 964.760 908.410 968.760 ;
    END
  END result_data[170]
  PIN result_data[171]
    DIRECTION OUTPUT TRISTATE ;
    USE SIGNAL ;
    ANTENNADIFFAREA 0.795200 ;
    PORT
      LAYER met3 ;
        RECT 0.000 404.640 4.000 405.240 ;
    END
  END result_data[171]
  PIN result_data[172]
    DIRECTION OUTPUT TRISTATE ;
    USE SIGNAL ;
    ANTENNADIFFAREA 0.795200 ;
    PORT
      LAYER met2 ;
        RECT 116.010 964.760 116.290 968.760 ;
    END
  END result_data[172]
  PIN result_data[173]
    DIRECTION OUTPUT TRISTATE ;
    USE SIGNAL ;
    ANTENNADIFFAREA 0.795200 ;
    PORT
      LAYER met2 ;
        RECT 103.130 964.760 103.410 968.760 ;
    END
  END result_data[173]
  PIN result_data[174]
    DIRECTION OUTPUT TRISTATE ;
    USE SIGNAL ;
    ANTENNADIFFAREA 0.795200 ;
    PORT
      LAYER met3 ;
        RECT 0.000 241.440 4.000 242.040 ;
    END
  END result_data[174]
  PIN result_data[175]
    DIRECTION OUTPUT TRISTATE ;
    USE SIGNAL ;
    ANTENNADIFFAREA 0.795200 ;
    PORT
      LAYER met2 ;
        RECT 814.750 0.000 815.030 4.000 ;
    END
  END result_data[175]
  PIN result_data[176]
    DIRECTION OUTPUT TRISTATE ;
    USE SIGNAL ;
    ANTENNADIFFAREA 0.795200 ;
    PORT
      LAYER met2 ;
        RECT 711.710 964.760 711.990 968.760 ;
    END
  END result_data[176]
  PIN result_data[177]
    DIRECTION OUTPUT TRISTATE ;
    USE SIGNAL ;
    ANTENNADIFFAREA 0.795200 ;
    PORT
      LAYER met2 ;
        RECT 444.450 964.760 444.730 968.760 ;
    END
  END result_data[177]
  PIN result_data[178]
    DIRECTION OUTPUT TRISTATE ;
    USE SIGNAL ;
    ANTENNADIFFAREA 0.795200 ;
    PORT
      LAYER met2 ;
        RECT 396.150 0.000 396.430 4.000 ;
    END
  END result_data[178]
  PIN result_data[179]
    DIRECTION OUTPUT TRISTATE ;
    USE SIGNAL ;
    ANTENNADIFFAREA 0.795200 ;
    PORT
      LAYER met3 ;
        RECT 0.000 299.240 4.000 299.840 ;
    END
  END result_data[179]
  PIN result_data[17]
    DIRECTION OUTPUT TRISTATE ;
    USE SIGNAL ;
    ANTENNADIFFAREA 0.445500 ;
    PORT
      LAYER met3 ;
        RECT 954.040 285.640 958.040 286.240 ;
    END
  END result_data[17]
  PIN result_data[180]
    DIRECTION OUTPUT TRISTATE ;
    USE SIGNAL ;
    ANTENNADIFFAREA 0.795200 ;
    PORT
      LAYER met2 ;
        RECT 821.190 964.760 821.470 968.760 ;
    END
  END result_data[180]
  PIN result_data[181]
    DIRECTION OUTPUT TRISTATE ;
    USE SIGNAL ;
    ANTENNADIFFAREA 0.795200 ;
    PORT
      LAYER met3 ;
        RECT 954.040 544.040 958.040 544.640 ;
    END
  END result_data[181]
  PIN result_data[182]
    DIRECTION OUTPUT TRISTATE ;
    USE SIGNAL ;
    ANTENNADIFFAREA 0.445500 ;
    PORT
      LAYER met3 ;
        RECT 954.040 948.640 958.040 949.240 ;
    END
  END result_data[182]
  PIN result_data[183]
    DIRECTION OUTPUT TRISTATE ;
    USE SIGNAL ;
    ANTENNADIFFAREA 0.445500 ;
    PORT
      LAYER met2 ;
        RECT 202.950 964.760 203.230 968.760 ;
    END
  END result_data[183]
  PIN result_data[184]
    DIRECTION OUTPUT TRISTATE ;
    USE SIGNAL ;
    ANTENNADIFFAREA 0.795200 ;
    PORT
      LAYER met3 ;
        RECT 0.000 149.640 4.000 150.240 ;
    END
  END result_data[184]
  PIN result_data[185]
    DIRECTION OUTPUT TRISTATE ;
    USE SIGNAL ;
    ANTENNADIFFAREA 0.795200 ;
    PORT
      LAYER met3 ;
        RECT 0.000 44.240 4.000 44.840 ;
    END
  END result_data[185]
  PIN result_data[186]
    DIRECTION OUTPUT TRISTATE ;
    USE SIGNAL ;
    ANTENNADIFFAREA 0.795200 ;
    PORT
      LAYER met2 ;
        RECT 6.530 964.760 6.810 968.760 ;
    END
  END result_data[186]
  PIN result_data[187]
    DIRECTION OUTPUT TRISTATE ;
    USE SIGNAL ;
    ANTENNADIFFAREA 0.795200 ;
    PORT
      LAYER met3 ;
        RECT 954.040 54.440 958.040 55.040 ;
    END
  END result_data[187]
  PIN result_data[188]
    DIRECTION OUTPUT TRISTATE ;
    USE SIGNAL ;
    ANTENNADIFFAREA 0.445500 ;
    PORT
      LAYER met3 ;
        RECT 954.040 683.440 958.040 684.040 ;
    END
  END result_data[188]
  PIN result_data[189]
    DIRECTION OUTPUT TRISTATE ;
    USE SIGNAL ;
    ANTENNADIFFAREA 0.795200 ;
    PORT
      LAYER met2 ;
        RECT 70.930 964.760 71.210 968.760 ;
    END
  END result_data[189]
  PIN result_data[18]
    DIRECTION OUTPUT TRISTATE ;
    USE SIGNAL ;
    ANTENNADIFFAREA 0.445500 ;
    PORT
      LAYER met3 ;
        RECT 954.040 217.640 958.040 218.240 ;
    END
  END result_data[18]
  PIN result_data[190]
    DIRECTION OUTPUT TRISTATE ;
    USE SIGNAL ;
    ANTENNADIFFAREA 0.795200 ;
    PORT
      LAYER met2 ;
        RECT 48.390 964.760 48.670 968.760 ;
    END
  END result_data[190]
  PIN result_data[191]
    DIRECTION OUTPUT TRISTATE ;
    USE SIGNAL ;
    ANTENNADIFFAREA 0.445500 ;
    PORT
      LAYER met3 ;
        RECT 954.040 414.840 958.040 415.440 ;
    END
  END result_data[191]
  PIN result_data[192]
    DIRECTION OUTPUT TRISTATE ;
    USE SIGNAL ;
    ANTENNADIFFAREA 0.795200 ;
    PORT
      LAYER met2 ;
        RECT 402.590 964.760 402.870 968.760 ;
    END
  END result_data[192]
  PIN result_data[193]
    DIRECTION OUTPUT TRISTATE ;
    USE SIGNAL ;
    ANTENNADIFFAREA 0.795200 ;
    PORT
      LAYER met2 ;
        RECT 605.450 0.000 605.730 4.000 ;
    END
  END result_data[193]
  PIN result_data[194]
    DIRECTION OUTPUT TRISTATE ;
    USE SIGNAL ;
    ANTENNADIFFAREA 0.795200 ;
    PORT
      LAYER met3 ;
        RECT 0.000 918.040 4.000 918.640 ;
    END
  END result_data[194]
  PIN result_data[195]
    DIRECTION OUTPUT TRISTATE ;
    USE SIGNAL ;
    ANTENNADIFFAREA 0.795200 ;
    PORT
      LAYER met2 ;
        RECT 582.910 0.000 583.190 4.000 ;
    END
  END result_data[195]
  PIN result_data[196]
    DIRECTION OUTPUT TRISTATE ;
    USE SIGNAL ;
    ANTENNADIFFAREA 0.795200 ;
    PORT
      LAYER met2 ;
        RECT 702.050 0.000 702.330 4.000 ;
    END
  END result_data[196]
  PIN result_data[197]
    DIRECTION OUTPUT TRISTATE ;
    USE SIGNAL ;
    ANTENNADIFFAREA 0.795200 ;
    PORT
      LAYER met2 ;
        RECT 119.230 0.000 119.510 4.000 ;
    END
  END result_data[197]
  PIN result_data[198]
    DIRECTION OUTPUT TRISTATE ;
    USE SIGNAL ;
    ANTENNADIFFAREA 0.795200 ;
    PORT
      LAYER met2 ;
        RECT 173.970 0.000 174.250 4.000 ;
    END
  END result_data[198]
  PIN result_data[199]
    DIRECTION OUTPUT TRISTATE ;
    USE SIGNAL ;
    ANTENNADIFFAREA 0.795200 ;
    PORT
      LAYER met2 ;
        RECT 666.630 964.760 666.910 968.760 ;
    END
  END result_data[199]
  PIN result_data[19]
    DIRECTION OUTPUT TRISTATE ;
    USE SIGNAL ;
    ANTENNADIFFAREA 0.795200 ;
    PORT
      LAYER met2 ;
        RECT 879.150 0.000 879.430 4.000 ;
    END
  END result_data[19]
  PIN result_data[1]
    DIRECTION OUTPUT TRISTATE ;
    USE SIGNAL ;
    ANTENNADIFFAREA 0.795200 ;
    PORT
      LAYER met3 ;
        RECT 954.040 275.440 958.040 276.040 ;
    END
  END result_data[1]
  PIN result_data[200]
    DIRECTION OUTPUT TRISTATE ;
    USE SIGNAL ;
    ANTENNADIFFAREA 0.795200 ;
    PORT
      LAYER met3 ;
        RECT 0.000 812.640 4.000 813.240 ;
    END
  END result_data[200]
  PIN result_data[201]
    DIRECTION OUTPUT TRISTATE ;
    USE SIGNAL ;
    ANTENNADIFFAREA 0.795200 ;
    PORT
      LAYER met3 ;
        RECT 954.040 799.040 958.040 799.640 ;
    END
  END result_data[201]
  PIN result_data[202]
    DIRECTION OUTPUT TRISTATE ;
    USE SIGNAL ;
    ANTENNADIFFAREA 0.795200 ;
    PORT
      LAYER met2 ;
        RECT 489.530 964.760 489.810 968.760 ;
    END
  END result_data[202]
  PIN result_data[203]
    DIRECTION OUTPUT TRISTATE ;
    USE SIGNAL ;
    ANTENNADIFFAREA 0.795200 ;
    PORT
      LAYER met2 ;
        RECT 228.710 0.000 228.990 4.000 ;
    END
  END result_data[203]
  PIN result_data[204]
    DIRECTION OUTPUT TRISTATE ;
    USE SIGNAL ;
    ANTENNADIFFAREA 0.795200 ;
    PORT
      LAYER met3 ;
        RECT 0.000 486.240 4.000 486.840 ;
    END
  END result_data[204]
  PIN result_data[205]
    DIRECTION OUTPUT TRISTATE ;
    USE SIGNAL ;
    ANTENNADIFFAREA 0.795200 ;
    PORT
      LAYER met3 ;
        RECT 0.000 312.840 4.000 313.440 ;
    END
  END result_data[205]
  PIN result_data[206]
    DIRECTION OUTPUT TRISTATE ;
    USE SIGNAL ;
    ANTENNADIFFAREA 0.795200 ;
    PORT
      LAYER met2 ;
        RECT 940.330 964.760 940.610 968.760 ;
    END
  END result_data[206]
  PIN result_data[207]
    DIRECTION OUTPUT TRISTATE ;
    USE SIGNAL ;
    ANTENNADIFFAREA 0.795200 ;
    PORT
      LAYER met3 ;
        RECT 0.000 683.440 4.000 684.040 ;
    END
  END result_data[207]
  PIN result_data[208]
    DIRECTION OUTPUT TRISTATE ;
    USE SIGNAL ;
    ANTENNADIFFAREA 0.445500 ;
    PORT
      LAYER met3 ;
        RECT 954.040 299.240 958.040 299.840 ;
    END
  END result_data[208]
  PIN result_data[209]
    DIRECTION OUTPUT TRISTATE ;
    USE SIGNAL ;
    ANTENNADIFFAREA 0.795200 ;
    PORT
      LAYER met3 ;
        RECT 954.040 669.840 958.040 670.440 ;
    END
  END result_data[209]
  PIN result_data[20]
    DIRECTION OUTPUT TRISTATE ;
    USE SIGNAL ;
    ANTENNADIFFAREA 0.795200 ;
    PORT
      LAYER met3 ;
        RECT 0.000 159.840 4.000 160.440 ;
    END
  END result_data[20]
  PIN result_data[210]
    DIRECTION OUTPUT TRISTATE ;
    USE SIGNAL ;
    ANTENNADIFFAREA 0.795200 ;
    PORT
      LAYER met2 ;
        RECT 280.230 964.760 280.510 968.760 ;
    END
  END result_data[210]
  PIN result_data[211]
    DIRECTION OUTPUT TRISTATE ;
    USE SIGNAL ;
    ANTENNADIFFAREA 0.795200 ;
    PORT
      LAYER met2 ;
        RECT 721.370 964.760 721.650 968.760 ;
    END
  END result_data[211]
  PIN result_data[212]
    DIRECTION OUTPUT TRISTATE ;
    USE SIGNAL ;
    ANTENNADIFFAREA 0.445500 ;
    PORT
      LAYER met3 ;
        RECT 954.040 567.840 958.040 568.440 ;
    END
  END result_data[212]
  PIN result_data[213]
    DIRECTION OUTPUT TRISTATE ;
    USE SIGNAL ;
    ANTENNADIFFAREA 0.795200 ;
    PORT
      LAYER met2 ;
        RECT 415.470 0.000 415.750 4.000 ;
    END
  END result_data[213]
  PIN result_data[214]
    DIRECTION OUTPUT TRISTATE ;
    USE SIGNAL ;
    ANTENNADIFFAREA 0.445500 ;
    PORT
      LAYER met3 ;
        RECT 954.040 833.040 958.040 833.640 ;
    END
  END result_data[214]
  PIN result_data[215]
    DIRECTION OUTPUT TRISTATE ;
    USE SIGNAL ;
    ANTENNADIFFAREA 0.795200 ;
    PORT
      LAYER met3 ;
        RECT 0.000 418.240 4.000 418.840 ;
    END
  END result_data[215]
  PIN result_data[216]
    DIRECTION OUTPUT TRISTATE ;
    USE SIGNAL ;
    ANTENNADIFFAREA 0.795200 ;
    PORT
      LAYER met2 ;
        RECT 9.750 0.000 10.030 4.000 ;
    END
  END result_data[216]
  PIN result_data[217]
    DIRECTION OUTPUT TRISTATE ;
    USE SIGNAL ;
    ANTENNADIFFAREA 0.795200 ;
    PORT
      LAYER met2 ;
        RECT 637.650 0.000 637.930 4.000 ;
    END
  END result_data[217]
  PIN result_data[218]
    DIRECTION OUTPUT TRISTATE ;
    USE SIGNAL ;
    ANTENNADIFFAREA 0.795200 ;
    PORT
      LAYER met2 ;
        RECT 428.350 0.000 428.630 4.000 ;
    END
  END result_data[218]
  PIN result_data[219]
    DIRECTION OUTPUT TRISTATE ;
    USE SIGNAL ;
    ANTENNADIFFAREA 0.795200 ;
    PORT
      LAYER met2 ;
        RECT 856.610 0.000 856.890 4.000 ;
    END
  END result_data[219]
  PIN result_data[21]
    DIRECTION OUTPUT TRISTATE ;
    USE SIGNAL ;
    ANTENNADIFFAREA 0.795200 ;
    PORT
      LAYER met3 ;
        RECT 954.040 788.840 958.040 789.440 ;
    END
  END result_data[21]
  PIN result_data[220]
    DIRECTION OUTPUT TRISTATE ;
    USE SIGNAL ;
    ANTENNADIFFAREA 0.795200 ;
    PORT
      LAYER met2 ;
        RECT 412.250 964.760 412.530 968.760 ;
    END
  END result_data[220]
  PIN result_data[221]
    DIRECTION OUTPUT TRISTATE ;
    USE SIGNAL ;
    ANTENNADIFFAREA 0.795200 ;
    PORT
      LAYER met3 ;
        RECT 0.000 78.240 4.000 78.840 ;
    END
  END result_data[221]
  PIN result_data[222]
    DIRECTION OUTPUT TRISTATE ;
    USE SIGNAL ;
    ANTENNADIFFAREA 0.795200 ;
    PORT
      LAYER met3 ;
        RECT 0.000 765.040 4.000 765.640 ;
    END
  END result_data[222]
  PIN result_data[223]
    DIRECTION OUTPUT TRISTATE ;
    USE SIGNAL ;
    ANTENNADIFFAREA 0.795200 ;
    PORT
      LAYER met2 ;
        RECT 164.310 0.000 164.590 4.000 ;
    END
  END result_data[223]
  PIN result_data[224]
    DIRECTION OUTPUT TRISTATE ;
    USE SIGNAL ;
    ANTENNADIFFAREA 0.795200 ;
    PORT
      LAYER met2 ;
        RECT 373.610 0.000 373.890 4.000 ;
    END
  END result_data[224]
  PIN result_data[225]
    DIRECTION OUTPUT TRISTATE ;
    USE SIGNAL ;
    ANTENNADIFFAREA 0.795200 ;
    PORT
      LAYER met2 ;
        RECT 83.810 964.760 84.090 968.760 ;
    END
  END result_data[225]
  PIN result_data[226]
    DIRECTION OUTPUT TRISTATE ;
    USE SIGNAL ;
    ANTENNADIFFAREA 0.795200 ;
    PORT
      LAYER met3 ;
        RECT 0.000 880.640 4.000 881.240 ;
    END
  END result_data[226]
  PIN result_data[227]
    DIRECTION OUTPUT TRISTATE ;
    USE SIGNAL ;
    ANTENNADIFFAREA 0.795200 ;
    PORT
      LAYER met2 ;
        RECT 318.870 0.000 319.150 4.000 ;
    END
  END result_data[227]
  PIN result_data[228]
    DIRECTION OUTPUT TRISTATE ;
    USE SIGNAL ;
    ANTENNADIFFAREA 0.795200 ;
    PORT
      LAYER met3 ;
        RECT 0.000 533.840 4.000 534.440 ;
    END
  END result_data[228]
  PIN result_data[229]
    DIRECTION OUTPUT TRISTATE ;
    USE SIGNAL ;
    ANTENNADIFFAREA 0.795200 ;
    PORT
      LAYER met3 ;
        RECT 954.040 309.440 958.040 310.040 ;
    END
  END result_data[229]
  PIN result_data[22]
    DIRECTION OUTPUT TRISTATE ;
    USE SIGNAL ;
    ANTENNADIFFAREA 0.795200 ;
    PORT
      LAYER met3 ;
        RECT 0.000 57.840 4.000 58.440 ;
    END
  END result_data[22]
  PIN result_data[230]
    DIRECTION OUTPUT TRISTATE ;
    USE SIGNAL ;
    ANTENNADIFFAREA 0.795200 ;
    PORT
      LAYER met2 ;
        RECT 434.790 964.760 435.070 968.760 ;
    END
  END result_data[230]
  PIN result_data[231]
    DIRECTION OUTPUT TRISTATE ;
    USE SIGNAL ;
    ANTENNADIFFAREA 0.795200 ;
    PORT
      LAYER met2 ;
        RECT 566.810 964.760 567.090 968.760 ;
    END
  END result_data[231]
  PIN result_data[232]
    DIRECTION OUTPUT TRISTATE ;
    USE SIGNAL ;
    ANTENNADIFFAREA 0.795200 ;
    PORT
      LAYER met2 ;
        RECT 834.070 0.000 834.350 4.000 ;
    END
  END result_data[232]
  PIN result_data[233]
    DIRECTION OUTPUT TRISTATE ;
    USE SIGNAL ;
    ANTENNADIFFAREA 0.445500 ;
    PORT
      LAYER met3 ;
        RECT 954.040 448.840 958.040 449.440 ;
    END
  END result_data[233]
  PIN result_data[234]
    DIRECTION OUTPUT TRISTATE ;
    USE SIGNAL ;
    ANTENNADIFFAREA 0.795200 ;
    PORT
      LAYER met3 ;
        RECT 0.000 68.040 4.000 68.640 ;
    END
  END result_data[234]
  PIN result_data[235]
    DIRECTION OUTPUT TRISTATE ;
    USE SIGNAL ;
    ANTENNADIFFAREA 0.795200 ;
    PORT
      LAYER met2 ;
        RECT 357.510 964.760 357.790 968.760 ;
    END
  END result_data[235]
  PIN result_data[236]
    DIRECTION OUTPUT TRISTATE ;
    USE SIGNAL ;
    ANTENNADIFFAREA 0.795200 ;
    PORT
      LAYER met2 ;
        RECT 647.310 0.000 647.590 4.000 ;
    END
  END result_data[236]
  PIN result_data[237]
    DIRECTION OUTPUT TRISTATE ;
    USE SIGNAL ;
    ANTENNADIFFAREA 0.445500 ;
    PORT
      LAYER met3 ;
        RECT 954.040 890.840 958.040 891.440 ;
    END
  END result_data[237]
  PIN result_data[238]
    DIRECTION OUTPUT TRISTATE ;
    USE SIGNAL ;
    ANTENNADIFFAREA 0.795200 ;
    PORT
      LAYER met2 ;
        RECT 933.890 0.000 934.170 4.000 ;
    END
  END result_data[238]
  PIN result_data[239]
    DIRECTION OUTPUT TRISTATE ;
    USE SIGNAL ;
    ANTENNADIFFAREA 0.795200 ;
    PORT
      LAYER met2 ;
        RECT 776.110 964.760 776.390 968.760 ;
    END
  END result_data[239]
  PIN result_data[23]
    DIRECTION OUTPUT TRISTATE ;
    USE SIGNAL ;
    ANTENNADIFFAREA 0.795200 ;
    PORT
      LAYER met2 ;
        RECT 792.210 0.000 792.490 4.000 ;
    END
  END result_data[23]
  PIN result_data[240]
    DIRECTION OUTPUT TRISTATE ;
    USE SIGNAL ;
    ANTENNADIFFAREA 0.795200 ;
    PORT
      LAYER met2 ;
        RECT 466.990 964.760 467.270 968.760 ;
    END
  END result_data[240]
  PIN result_data[241]
    DIRECTION OUTPUT TRISTATE ;
    USE SIGNAL ;
    ANTENNADIFFAREA 0.795200 ;
    PORT
      LAYER met2 ;
        RECT 109.570 0.000 109.850 4.000 ;
    END
  END result_data[241]
  PIN result_data[242]
    DIRECTION OUTPUT TRISTATE ;
    USE SIGNAL ;
    ANTENNADIFFAREA 0.445500 ;
    PORT
      LAYER met3 ;
        RECT 954.040 346.840 958.040 347.440 ;
    END
  END result_data[242]
  PIN result_data[243]
    DIRECTION OUTPUT TRISTATE ;
    USE SIGNAL ;
    ANTENNADIFFAREA 0.795200 ;
    PORT
      LAYER met3 ;
        RECT 0.000 649.440 4.000 650.040 ;
    END
  END result_data[243]
  PIN result_data[244]
    DIRECTION OUTPUT TRISTATE ;
    USE SIGNAL ;
    ANTENNADIFFAREA 0.795200 ;
    PORT
      LAYER met3 ;
        RECT 954.040 496.440 958.040 497.040 ;
    END
  END result_data[244]
  PIN result_data[245]
    DIRECTION OUTPUT TRISTATE ;
    USE SIGNAL ;
    ANTENNADIFFAREA 0.795200 ;
    PORT
      LAYER met2 ;
        RECT 219.050 0.000 219.330 4.000 ;
    END
  END result_data[245]
  PIN result_data[246]
    DIRECTION OUTPUT TRISTATE ;
    USE SIGNAL ;
    ANTENNADIFFAREA 0.795200 ;
    PORT
      LAYER met2 ;
        RECT 824.410 0.000 824.690 4.000 ;
    END
  END result_data[246]
  PIN result_data[247]
    DIRECTION OUTPUT TRISTATE ;
    USE SIGNAL ;
    ANTENNADIFFAREA 0.795200 ;
    PORT
      LAYER met2 ;
        RECT 502.410 964.760 502.690 968.760 ;
    END
  END result_data[247]
  PIN result_data[248]
    DIRECTION OUTPUT TRISTATE ;
    USE SIGNAL ;
    ANTENNADIFFAREA 0.795200 ;
    PORT
      LAYER met3 ;
        RECT 0.000 659.640 4.000 660.240 ;
    END
  END result_data[248]
  PIN result_data[249]
    DIRECTION OUTPUT TRISTATE ;
    USE SIGNAL ;
    ANTENNADIFFAREA 0.795200 ;
    PORT
      LAYER met3 ;
        RECT 954.040 601.840 958.040 602.440 ;
    END
  END result_data[249]
  PIN result_data[24]
    DIRECTION OUTPUT TRISTATE ;
    USE SIGNAL ;
    ANTENNADIFFAREA 0.795200 ;
    PORT
      LAYER met2 ;
        RECT 457.330 964.760 457.610 968.760 ;
    END
  END result_data[24]
  PIN result_data[250]
    DIRECTION OUTPUT TRISTATE ;
    USE SIGNAL ;
    ANTENNADIFFAREA 0.795200 ;
    PORT
      LAYER met2 ;
        RECT 521.730 964.760 522.010 968.760 ;
    END
  END result_data[250]
  PIN result_data[251]
    DIRECTION OUTPUT TRISTATE ;
    USE SIGNAL ;
    ANTENNADIFFAREA 0.795200 ;
    PORT
      LAYER met3 ;
        RECT 954.040 68.040 958.040 68.640 ;
    END
  END result_data[251]
  PIN result_data[252]
    DIRECTION OUTPUT TRISTATE ;
    USE SIGNAL ;
    ANTENNADIFFAREA 0.795200 ;
    PORT
      LAYER met2 ;
        RECT 389.710 964.760 389.990 968.760 ;
    END
  END result_data[252]
  PIN result_data[253]
    DIRECTION OUTPUT TRISTATE ;
    USE SIGNAL ;
    ANTENNADIFFAREA 0.795200 ;
    PORT
      LAYER met3 ;
        RECT 954.040 227.840 958.040 228.440 ;
    END
  END result_data[253]
  PIN result_data[254]
    DIRECTION OUTPUT TRISTATE ;
    USE SIGNAL ;
    ANTENNADIFFAREA 0.795200 ;
    PORT
      LAYER met2 ;
        RECT 798.650 964.760 798.930 968.760 ;
    END
  END result_data[254]
  PIN result_data[255]
    DIRECTION OUTPUT TRISTATE ;
    USE SIGNAL ;
    ANTENNADIFFAREA 0.795200 ;
    PORT
      LAYER met2 ;
        RECT 611.890 964.760 612.170 968.760 ;
    END
  END result_data[255]
  PIN result_data[25]
    DIRECTION OUTPUT TRISTATE ;
    USE SIGNAL ;
    ANTENNADIFFAREA 0.795200 ;
    PORT
      LAYER met2 ;
        RECT 270.570 964.760 270.850 968.760 ;
    END
  END result_data[25]
  PIN result_data[26]
    DIRECTION OUTPUT TRISTATE ;
    USE SIGNAL ;
    ANTENNADIFFAREA 0.795200 ;
    PORT
      LAYER met3 ;
        RECT 0.000 438.640 4.000 439.240 ;
    END
  END result_data[26]
  PIN result_data[27]
    DIRECTION OUTPUT TRISTATE ;
    USE SIGNAL ;
    ANTENNADIFFAREA 0.795200 ;
    PORT
      LAYER met2 ;
        RECT 29.070 964.760 29.350 968.760 ;
    END
  END result_data[27]
  PIN result_data[28]
    DIRECTION OUTPUT TRISTATE ;
    USE SIGNAL ;
    ANTENNADIFFAREA 0.445500 ;
    PORT
      LAYER met3 ;
        RECT 954.040 588.240 958.040 588.840 ;
    END
  END result_data[28]
  PIN result_data[29]
    DIRECTION OUTPUT TRISTATE ;
    USE SIGNAL ;
    ANTENNADIFFAREA 0.795200 ;
    PORT
      LAYER met3 ;
        RECT 0.000 567.840 4.000 568.440 ;
    END
  END result_data[29]
  PIN result_data[2]
    DIRECTION OUTPUT TRISTATE ;
    USE SIGNAL ;
    ANTENNADIFFAREA 0.795200 ;
    PORT
      LAYER met3 ;
        RECT 0.000 125.840 4.000 126.440 ;
    END
  END result_data[2]
  PIN result_data[30]
    DIRECTION OUTPUT TRISTATE ;
    USE SIGNAL ;
    ANTENNADIFFAREA 0.795200 ;
    PORT
      LAYER met3 ;
        RECT 0.000 788.840 4.000 789.440 ;
    END
  END result_data[30]
  PIN result_data[31]
    DIRECTION OUTPUT TRISTATE ;
    USE SIGNAL ;
    ANTENNADIFFAREA 0.795200 ;
    PORT
      LAYER met3 ;
        RECT 954.040 207.440 958.040 208.040 ;
    END
  END result_data[31]
  PIN result_data[32]
    DIRECTION OUTPUT TRISTATE ;
    USE SIGNAL ;
    ANTENNADIFFAREA 0.795200 ;
    PORT
      LAYER met2 ;
        RECT 846.950 0.000 847.230 4.000 ;
    END
  END result_data[32]
  PIN result_data[33]
    DIRECTION OUTPUT TRISTATE ;
    USE SIGNAL ;
    ANTENNADIFFAREA 0.795200 ;
    PORT
      LAYER met3 ;
        RECT 0.000 394.440 4.000 395.040 ;
    END
  END result_data[33]
  PIN result_data[34]
    DIRECTION OUTPUT TRISTATE ;
    USE SIGNAL ;
    ANTENNADIFFAREA 0.445500 ;
    PORT
      LAYER met3 ;
        RECT 954.040 914.640 958.040 915.240 ;
    END
  END result_data[34]
  PIN result_data[35]
    DIRECTION OUTPUT TRISTATE ;
    USE SIGNAL ;
    ANTENNADIFFAREA 0.795200 ;
    PORT
      LAYER met2 ;
        RECT 492.750 0.000 493.030 4.000 ;
    END
  END result_data[35]
  PIN result_data[36]
    DIRECTION OUTPUT TRISTATE ;
    USE SIGNAL ;
    ANTENNADIFFAREA 0.795200 ;
    PORT
      LAYER met2 ;
        RECT 714.930 0.000 715.210 4.000 ;
    END
  END result_data[36]
  PIN result_data[37]
    DIRECTION OUTPUT TRISTATE ;
    USE SIGNAL ;
    ANTENNADIFFAREA 0.445500 ;
    PORT
      LAYER met3 ;
        RECT 954.040 136.040 958.040 136.640 ;
    END
  END result_data[37]
  PIN result_data[38]
    DIRECTION OUTPUT TRISTATE ;
    USE SIGNAL ;
    ANTENNADIFFAREA 0.445500 ;
    PORT
      LAYER met2 ;
        RECT 293.110 964.760 293.390 968.760 ;
    END
  END result_data[38]
  PIN result_data[39]
    DIRECTION OUTPUT TRISTATE ;
    USE SIGNAL ;
    ANTENNADIFFAREA 0.795200 ;
    PORT
      LAYER met2 ;
        RECT 483.090 0.000 483.370 4.000 ;
    END
  END result_data[39]
  PIN result_data[3]
    DIRECTION OUTPUT TRISTATE ;
    USE SIGNAL ;
    ANTENNADIFFAREA 0.795200 ;
    PORT
      LAYER met2 ;
        RECT 87.030 0.000 87.310 4.000 ;
    END
  END result_data[3]
  PIN result_data[40]
    DIRECTION OUTPUT TRISTATE ;
    USE SIGNAL ;
    ANTENNADIFFAREA 0.795200 ;
    PORT
      LAYER met2 ;
        RECT 479.870 964.760 480.150 968.760 ;
    END
  END result_data[40]
  PIN result_data[41]
    DIRECTION OUTPUT TRISTATE ;
    USE SIGNAL ;
    ANTENNADIFFAREA 0.445500 ;
    PORT
      LAYER met3 ;
        RECT 954.040 472.640 958.040 473.240 ;
    END
  END result_data[41]
  PIN result_data[42]
    DIRECTION OUTPUT TRISTATE ;
    USE SIGNAL ;
    ANTENNADIFFAREA 0.795200 ;
    PORT
      LAYER met3 ;
        RECT 0.000 462.440 4.000 463.040 ;
    END
  END result_data[42]
  PIN result_data[43]
    DIRECTION OUTPUT TRISTATE ;
    USE SIGNAL ;
    ANTENNADIFFAREA 0.795200 ;
    PORT
      LAYER met2 ;
        RECT 341.410 0.000 341.690 4.000 ;
    END
  END result_data[43]
  PIN result_data[44]
    DIRECTION OUTPUT TRISTATE ;
    USE SIGNAL ;
    ANTENNADIFFAREA 0.795200 ;
    PORT
      LAYER met3 ;
        RECT 0.000 601.840 4.000 602.440 ;
    END
  END result_data[44]
  PIN result_data[45]
    DIRECTION OUTPUT TRISTATE ;
    USE SIGNAL ;
    ANTENNADIFFAREA 0.445500 ;
    PORT
      LAYER met3 ;
        RECT 954.040 323.040 958.040 323.640 ;
    END
  END result_data[45]
  PIN result_data[46]
    DIRECTION OUTPUT TRISTATE ;
    USE SIGNAL ;
    ANTENNADIFFAREA 0.795200 ;
    PORT
      LAYER met2 ;
        RECT 692.390 0.000 692.670 4.000 ;
    END
  END result_data[46]
  PIN result_data[47]
    DIRECTION OUTPUT TRISTATE ;
    USE SIGNAL ;
    ANTENNADIFFAREA 0.795200 ;
    PORT
      LAYER met2 ;
        RECT 843.730 964.760 844.010 968.760 ;
    END
  END result_data[47]
  PIN result_data[48]
    DIRECTION OUTPUT TRISTATE ;
    USE SIGNAL ;
    ANTENNADIFFAREA 0.795200 ;
    PORT
      LAYER met2 ;
        RECT 669.850 0.000 670.130 4.000 ;
    END
  END result_data[48]
  PIN result_data[49]
    DIRECTION OUTPUT TRISTATE ;
    USE SIGNAL ;
    ANTENNADIFFAREA 0.795200 ;
    PORT
      LAYER met3 ;
        RECT 0.000 578.040 4.000 578.640 ;
    END
  END result_data[49]
  PIN result_data[4]
    DIRECTION OUTPUT TRISTATE ;
    USE SIGNAL ;
    ANTENNADIFFAREA 0.795200 ;
    PORT
      LAYER met2 ;
        RECT 41.950 0.000 42.230 4.000 ;
    END
  END result_data[4]
  PIN result_data[50]
    DIRECTION OUTPUT TRISTATE ;
    USE SIGNAL ;
    ANTENNADIFFAREA 0.795200 ;
    PORT
      LAYER met2 ;
        RECT 888.810 0.000 889.090 4.000 ;
    END
  END result_data[50]
  PIN result_data[51]
    DIRECTION OUTPUT TRISTATE ;
    USE SIGNAL ;
    ANTENNADIFFAREA 0.445500 ;
    PORT
      LAYER met3 ;
        RECT 954.040 193.840 958.040 194.440 ;
    END
  END result_data[51]
  PIN result_data[52]
    DIRECTION OUTPUT TRISTATE ;
    USE SIGNAL ;
    ANTENNADIFFAREA 0.795200 ;
    PORT
      LAYER met2 ;
        RECT 425.130 964.760 425.410 968.760 ;
    END
  END result_data[52]
  PIN result_data[53]
    DIRECTION OUTPUT TRISTATE ;
    USE SIGNAL ;
    ANTENNADIFFAREA 0.795200 ;
    PORT
      LAYER met3 ;
        RECT 954.040 765.040 958.040 765.640 ;
    END
  END result_data[53]
  PIN result_data[54]
    DIRECTION OUTPUT TRISTATE ;
    USE SIGNAL ;
    ANTENNADIFFAREA 0.795200 ;
    PORT
      LAYER met3 ;
        RECT 0.000 289.040 4.000 289.640 ;
    END
  END result_data[54]
  PIN result_data[55]
    DIRECTION OUTPUT TRISTATE ;
    USE SIGNAL ;
    ANTENNADIFFAREA 0.795200 ;
    PORT
      LAYER met3 ;
        RECT 0.000 962.240 4.000 962.840 ;
    END
  END result_data[55]
  PIN result_data[56]
    DIRECTION OUTPUT TRISTATE ;
    USE SIGNAL ;
    ANTENNADIFFAREA 0.795200 ;
    PORT
      LAYER met3 ;
        RECT 0.000 938.440 4.000 939.040 ;
    END
  END result_data[56]
  PIN result_data[57]
    DIRECTION OUTPUT TRISTATE ;
    USE SIGNAL ;
    ANTENNADIFFAREA 0.795200 ;
    PORT
      LAYER met2 ;
        RECT 32.290 0.000 32.570 4.000 ;
    END
  END result_data[57]
  PIN result_data[58]
    DIRECTION OUTPUT TRISTATE ;
    USE SIGNAL ;
    ANTENNADIFFAREA 0.795200 ;
    PORT
      LAYER met3 ;
        RECT 0.000 255.040 4.000 255.640 ;
    END
  END result_data[58]
  PIN result_data[59]
    DIRECTION OUTPUT TRISTATE ;
    USE SIGNAL ;
    ANTENNADIFFAREA 0.445500 ;
    PORT
      LAYER met3 ;
        RECT 954.040 438.640 958.040 439.240 ;
    END
  END result_data[59]
  PIN result_data[5]
    DIRECTION OUTPUT TRISTATE ;
    USE SIGNAL ;
    ANTENNADIFFAREA 0.795200 ;
    PORT
      LAYER met2 ;
        RECT 515.290 0.000 515.570 4.000 ;
    END
  END result_data[5]
  PIN result_data[60]
    DIRECTION OUTPUT TRISTATE ;
    USE SIGNAL ;
    ANTENNADIFFAREA 0.795200 ;
    PORT
      LAYER met2 ;
        RECT 743.910 964.760 744.190 968.760 ;
    END
  END result_data[60]
  PIN result_data[61]
    DIRECTION OUTPUT TRISTATE ;
    USE SIGNAL ;
    ANTENNADIFFAREA 0.795200 ;
    PORT
      LAYER met3 ;
        RECT 954.040 962.240 958.040 962.840 ;
    END
  END result_data[61]
  PIN result_data[62]
    DIRECTION OUTPUT TRISTATE ;
    USE SIGNAL ;
    ANTENNADIFFAREA 0.795200 ;
    PORT
      LAYER met2 ;
        RECT 170.750 964.760 171.030 968.760 ;
    END
  END result_data[62]
  PIN result_data[63]
    DIRECTION OUTPUT TRISTATE ;
    USE SIGNAL ;
    ANTENNADIFFAREA 0.795200 ;
    PORT
      LAYER met3 ;
        RECT 0.000 510.040 4.000 510.640 ;
    END
  END result_data[63]
  PIN result_data[64]
    DIRECTION OUTPUT TRISTATE ;
    USE SIGNAL ;
    ANTENNADIFFAREA 0.445500 ;
    PORT
      LAYER met3 ;
        RECT 954.040 520.240 958.040 520.840 ;
    END
  END result_data[64]
  PIN result_data[65]
    DIRECTION OUTPUT TRISTATE ;
    USE SIGNAL ;
    ANTENNADIFFAREA 0.445500 ;
    PORT
      LAYER met3 ;
        RECT 954.040 938.440 958.040 939.040 ;
    END
  END result_data[65]
  PIN result_data[66]
    DIRECTION OUTPUT TRISTATE ;
    USE SIGNAL ;
    ANTENNADIFFAREA 0.795200 ;
    PORT
      LAYER met3 ;
        RECT 0.000 697.040 4.000 697.640 ;
    END
  END result_data[66]
  PIN result_data[67]
    DIRECTION OUTPUT TRISTATE ;
    USE SIGNAL ;
    ANTENNADIFFAREA 0.795200 ;
    PORT
      LAYER met3 ;
        RECT 954.040 693.640 958.040 694.240 ;
    END
  END result_data[67]
  PIN result_data[68]
    DIRECTION OUTPUT TRISTATE ;
    USE SIGNAL ;
    ANTENNADIFFAREA 0.795200 ;
    PORT
      LAYER met3 ;
        RECT 954.040 265.240 958.040 265.840 ;
    END
  END result_data[68]
  PIN result_data[69]
    DIRECTION OUTPUT TRISTATE ;
    USE SIGNAL ;
    ANTENNADIFFAREA 0.795200 ;
    PORT
      LAYER met3 ;
        RECT 0.000 357.040 4.000 357.640 ;
    END
  END result_data[69]
  PIN result_data[6]
    DIRECTION OUTPUT TRISTATE ;
    USE SIGNAL ;
    ANTENNADIFFAREA 0.795200 ;
    PORT
      LAYER met2 ;
        RECT 863.050 964.760 863.330 968.760 ;
    END
  END result_data[6]
  PIN result_data[70]
    DIRECTION OUTPUT TRISTATE ;
    USE SIGNAL ;
    ANTENNADIFFAREA 0.795200 ;
    PORT
      LAYER met3 ;
        RECT 0.000 34.040 4.000 34.640 ;
    END
  END result_data[70]
  PIN result_data[71]
    DIRECTION OUTPUT TRISTATE ;
    USE SIGNAL ;
    ANTENNADIFFAREA 0.795200 ;
    PORT
      LAYER met2 ;
        RECT 283.450 0.000 283.730 4.000 ;
    END
  END result_data[71]
  PIN result_data[72]
    DIRECTION OUTPUT TRISTATE ;
    USE SIGNAL ;
    ANTENNADIFFAREA 0.445500 ;
    PORT
      LAYER met3 ;
        RECT 954.040 530.440 958.040 531.040 ;
    END
  END result_data[72]
  PIN result_data[73]
    DIRECTION OUTPUT TRISTATE ;
    USE SIGNAL ;
    ANTENNADIFFAREA 0.795200 ;
    PORT
      LAYER met2 ;
        RECT 747.130 0.000 747.410 4.000 ;
    END
  END result_data[73]
  PIN result_data[74]
    DIRECTION OUTPUT TRISTATE ;
    USE SIGNAL ;
    ANTENNADIFFAREA 0.795200 ;
    PORT
      LAYER met3 ;
        RECT 0.000 183.640 4.000 184.240 ;
    END
  END result_data[74]
  PIN result_data[75]
    DIRECTION OUTPUT TRISTATE ;
    USE SIGNAL ;
    ANTENNADIFFAREA 0.795200 ;
    PORT
      LAYER met3 ;
        RECT 0.000 615.440 4.000 616.040 ;
    END
  END result_data[75]
  PIN result_data[76]
    DIRECTION OUTPUT TRISTATE ;
    USE SIGNAL ;
    ANTENNADIFFAREA 0.795200 ;
    PORT
      LAYER met2 ;
        RECT 946.770 0.000 947.050 4.000 ;
    END
  END result_data[76]
  PIN result_data[77]
    DIRECTION OUTPUT TRISTATE ;
    USE SIGNAL ;
    ANTENNADIFFAREA 0.795200 ;
    PORT
      LAYER met2 ;
        RECT 141.770 0.000 142.050 4.000 ;
    END
  END result_data[77]
  PIN result_data[78]
    DIRECTION OUTPUT TRISTATE ;
    USE SIGNAL ;
    ANTENNADIFFAREA 0.795200 ;
    PORT
      LAYER met2 ;
        RECT 450.890 0.000 451.170 4.000 ;
    END
  END result_data[78]
  PIN result_data[79]
    DIRECTION OUTPUT TRISTATE ;
    USE SIGNAL ;
    ANTENNADIFFAREA 0.795200 ;
    PORT
      LAYER met3 ;
        RECT 954.040 367.240 958.040 367.840 ;
    END
  END result_data[79]
  PIN result_data[7]
    DIRECTION OUTPUT TRISTATE ;
    USE SIGNAL ;
    ANTENNADIFFAREA 0.795200 ;
    PORT
      LAYER met2 ;
        RECT 808.310 964.760 808.590 968.760 ;
    END
  END result_data[7]
  PIN result_data[80]
    DIRECTION OUTPUT TRISTATE ;
    USE SIGNAL ;
    ANTENNADIFFAREA 0.795200 ;
    PORT
      LAYER met3 ;
        RECT 954.040 822.840 958.040 823.440 ;
    END
  END result_data[80]
  PIN result_data[81]
    DIRECTION OUTPUT TRISTATE ;
    USE SIGNAL ;
    ANTENNADIFFAREA 0.795200 ;
    PORT
      LAYER met3 ;
        RECT 954.040 6.840 958.040 7.440 ;
    END
  END result_data[81]
  PIN result_data[82]
    DIRECTION OUTPUT TRISTATE ;
    USE SIGNAL ;
    ANTENNADIFFAREA 0.795200 ;
    PORT
      LAYER met2 ;
        RECT 74.150 0.000 74.430 4.000 ;
    END
  END result_data[82]
  PIN result_data[83]
    DIRECTION OUTPUT TRISTATE ;
    USE SIGNAL ;
    ANTENNADIFFAREA 0.445500 ;
    PORT
      LAYER met3 ;
        RECT 954.040 506.640 958.040 507.240 ;
    END
  END result_data[83]
  PIN result_data[84]
    DIRECTION OUTPUT TRISTATE ;
    USE SIGNAL ;
    ANTENNADIFFAREA 0.795200 ;
    PORT
      LAYER met2 ;
        RECT 19.410 0.000 19.690 4.000 ;
    END
  END result_data[84]
  PIN result_data[85]
    DIRECTION OUTPUT TRISTATE ;
    USE SIGNAL ;
    ANTENNADIFFAREA 0.445500 ;
    PORT
      LAYER met3 ;
        RECT 954.040 856.840 958.040 857.440 ;
    END
  END result_data[85]
  PIN result_data[86]
    DIRECTION OUTPUT TRISTATE ;
    USE SIGNAL ;
    ANTENNADIFFAREA 0.795200 ;
    PORT
      LAYER met2 ;
        RECT 766.450 964.760 766.730 968.760 ;
    END
  END result_data[86]
  PIN result_data[87]
    DIRECTION OUTPUT TRISTATE ;
    USE SIGNAL ;
    ANTENNADIFFAREA 0.445500 ;
    PORT
      LAYER met3 ;
        RECT 954.040 78.240 958.040 78.840 ;
    END
  END result_data[87]
  PIN result_data[88]
    DIRECTION OUTPUT TRISTATE ;
    USE SIGNAL ;
    ANTENNADIFFAREA 0.795200 ;
    PORT
      LAYER met2 ;
        RECT 731.030 964.760 731.310 968.760 ;
    END
  END result_data[88]
  PIN result_data[89]
    DIRECTION OUTPUT TRISTATE ;
    USE SIGNAL ;
    ANTENNADIFFAREA 0.795200 ;
    PORT
      LAYER met2 ;
        RECT 624.770 0.000 625.050 4.000 ;
    END
  END result_data[89]
  PIN result_data[8]
    DIRECTION OUTPUT TRISTATE ;
    USE SIGNAL ;
    ANTENNADIFFAREA 0.795200 ;
    PORT
      LAYER met3 ;
        RECT 0.000 265.240 4.000 265.840 ;
    END
  END result_data[8]
  PIN result_data[90]
    DIRECTION OUTPUT TRISTATE ;
    USE SIGNAL ;
    ANTENNADIFFAREA 0.795200 ;
    PORT
      LAYER met2 ;
        RECT 615.110 0.000 615.390 4.000 ;
    END
  END result_data[90]
  PIN result_data[91]
    DIRECTION OUTPUT TRISTATE ;
    USE SIGNAL ;
    ANTENNADIFFAREA 0.795200 ;
    PORT
      LAYER met2 ;
        RECT 0.090 0.000 0.370 4.000 ;
    END
  END result_data[91]
  PIN result_data[92]
    DIRECTION OUTPUT TRISTATE ;
    USE SIGNAL ;
    ANTENNADIFFAREA 0.795200 ;
    PORT
      LAYER met2 ;
        RECT 724.590 0.000 724.870 4.000 ;
    END
  END result_data[92]
  PIN result_data[93]
    DIRECTION OUTPUT TRISTATE ;
    USE SIGNAL ;
    ANTENNADIFFAREA 0.795200 ;
    PORT
      LAYER met3 ;
        RECT 0.000 520.240 4.000 520.840 ;
    END
  END result_data[93]
  PIN result_data[94]
    DIRECTION OUTPUT TRISTATE ;
    USE SIGNAL ;
    ANTENNADIFFAREA 0.795200 ;
    PORT
      LAYER met3 ;
        RECT 0.000 904.440 4.000 905.040 ;
    END
  END result_data[94]
  PIN result_data[95]
    DIRECTION OUTPUT TRISTATE ;
    USE SIGNAL ;
    ANTENNADIFFAREA 0.795200 ;
    PORT
      LAYER met2 ;
        RECT 312.430 964.760 312.710 968.760 ;
    END
  END result_data[95]
  PIN result_data[96]
    DIRECTION OUTPUT TRISTATE ;
    USE SIGNAL ;
    ANTENNADIFFAREA 0.795200 ;
    PORT
      LAYER met3 ;
        RECT 0.000 370.640 4.000 371.240 ;
    END
  END result_data[96]
  PIN result_data[97]
    DIRECTION OUTPUT TRISTATE ;
    USE SIGNAL ;
    ANTENNADIFFAREA 0.795200 ;
    PORT
      LAYER met2 ;
        RECT 196.510 0.000 196.790 4.000 ;
    END
  END result_data[97]
  PIN result_data[98]
    DIRECTION OUTPUT TRISTATE ;
    USE SIGNAL ;
    ANTENNADIFFAREA 0.795200 ;
    PORT
      LAYER met2 ;
        RECT 64.490 0.000 64.770 4.000 ;
    END
  END result_data[98]
  PIN result_data[99]
    DIRECTION OUTPUT TRISTATE ;
    USE SIGNAL ;
    ANTENNADIFFAREA 0.795200 ;
    PORT
      LAYER met2 ;
        RECT 534.610 964.760 534.890 968.760 ;
    END
  END result_data[99]
  PIN result_data[9]
    DIRECTION OUTPUT TRISTATE ;
    USE SIGNAL ;
    ANTENNADIFFAREA 0.795200 ;
    PORT
      LAYER met2 ;
        RECT 325.310 964.760 325.590 968.760 ;
    END
  END result_data[9]
  PIN result_ready
    DIRECTION INPUT ;
    USE SIGNAL ;
    ANTENNAGATEAREA 0.682200 ;
    ANTENNADIFFAREA 0.434700 ;
    PORT
      LAYER met2 ;
        RECT 505.630 0.000 505.910 4.000 ;
    END
  END result_ready
  PIN result_valid
    DIRECTION OUTPUT TRISTATE ;
    USE SIGNAL ;
    ANTENNADIFFAREA 0.795200 ;
    PORT
      LAYER met2 ;
        RECT 689.170 964.760 689.450 968.760 ;
    END
  END result_valid
  PIN rst_n
    DIRECTION INPUT ;
    USE SIGNAL ;
    ANTENNAGATEAREA 0.682200 ;
    ANTENNADIFFAREA 0.434700 ;
    PORT
      LAYER met3 ;
        RECT 954.040 241.440 958.040 242.040 ;
    END
  END rst_n
  PIN weight_addr[0]
    DIRECTION INPUT ;
    USE SIGNAL ;
    ANTENNAGATEAREA 0.929700 ;
    ANTENNADIFFAREA 0.434700 ;
    PORT
      LAYER met3 ;
        RECT 0.000 673.240 4.000 673.840 ;
    END
  END weight_addr[0]
  PIN weight_addr[1]
    DIRECTION INPUT ;
    USE SIGNAL ;
    ANTENNAGATEAREA 1.177200 ;
    ANTENNADIFFAREA 0.434700 ;
    PORT
      LAYER met3 ;
        RECT 954.040 727.640 958.040 728.240 ;
    END
  END weight_addr[1]
  PIN weight_addr[2]
    DIRECTION INPUT ;
    USE SIGNAL ;
    ANTENNAGATEAREA 0.860700 ;
    ANTENNADIFFAREA 0.434700 ;
    PORT
      LAYER met2 ;
        RECT 206.170 0.000 206.450 4.000 ;
    END
  END weight_addr[2]
  PIN weight_addr[3]
    DIRECTION INPUT ;
    USE SIGNAL ;
    ANTENNAGATEAREA 0.682200 ;
    ANTENNADIFFAREA 0.434700 ;
    PORT
      LAYER met2 ;
        RECT 351.070 0.000 351.350 4.000 ;
    END
  END weight_addr[3]
  PIN weight_addr[4]
    DIRECTION INPUT ;
    USE SIGNAL ;
    ANTENNAGATEAREA 1.177200 ;
    ANTENNADIFFAREA 0.434700 ;
    PORT
      LAYER met3 ;
        RECT 0.000 102.040 4.000 102.640 ;
    END
  END weight_addr[4]
  PIN weight_addr[5]
    DIRECTION INPUT ;
    USE SIGNAL ;
    ANTENNAGATEAREA 0.929700 ;
    ANTENNADIFFAREA 0.434700 ;
    PORT
      LAYER met3 ;
        RECT 954.040 707.240 958.040 707.840 ;
    END
  END weight_addr[5]
  PIN weight_data[0]
    DIRECTION INPUT ;
    USE SIGNAL ;
    ANTENNAGATEAREA 1.424700 ;
    ANTENNADIFFAREA 0.434700 ;
    PORT
      LAYER met2 ;
        RECT 560.370 0.000 560.650 4.000 ;
    END
  END weight_data[0]
  PIN weight_data[1]
    DIRECTION INPUT ;
    USE SIGNAL ;
    ANTENNAGATEAREA 1.424700 ;
    ANTENNADIFFAREA 0.434700 ;
    PORT
      LAYER met2 ;
        RECT 644.090 964.760 644.370 968.760 ;
    END
  END weight_data[1]
  PIN weight_data[2]
    DIRECTION INPUT ;
    USE SIGNAL ;
    ANTENNAGATEAREA 1.424700 ;
    ANTENNADIFFAREA 0.434700 ;
    PORT
      LAYER met2 ;
        RECT 634.430 964.760 634.710 968.760 ;
    END
  END weight_data[2]
  PIN weight_data[3]
    DIRECTION INPUT ;
    USE SIGNAL ;
    ANTENNAGATEAREA 1.424700 ;
    ANTENNADIFFAREA 0.434700 ;
    PORT
      LAYER met3 ;
        RECT 0.000 928.240 4.000 928.840 ;
    END
  END weight_data[3]
  PIN weight_data[4]
    DIRECTION INPUT ;
    USE SIGNAL ;
    ANTENNAGATEAREA 1.424700 ;
    ANTENNADIFFAREA 0.434700 ;
    PORT
      LAYER met2 ;
        RECT 125.670 964.760 125.950 968.760 ;
    END
  END weight_data[4]
  PIN weight_data[5]
    DIRECTION INPUT ;
    USE SIGNAL ;
    ANTENNAGATEAREA 1.424700 ;
    ANTENNADIFFAREA 0.434700 ;
    PORT
      LAYER met2 ;
        RECT 682.730 0.000 683.010 4.000 ;
    END
  END weight_data[5]
  PIN weight_data[6]
    DIRECTION INPUT ;
    USE SIGNAL ;
    ANTENNAGATEAREA 1.424700 ;
    ANTENNADIFFAREA 0.434700 ;
    PORT
      LAYER met3 ;
        RECT 0.000 217.640 4.000 218.240 ;
    END
  END weight_data[6]
  PIN weight_data[7]
    DIRECTION INPUT ;
    USE SIGNAL ;
    ANTENNAGATEAREA 1.424700 ;
    ANTENNADIFFAREA 0.434700 ;
    PORT
      LAYER met3 ;
        RECT 0.000 822.840 4.000 823.440 ;
    END
  END weight_data[7]
  PIN weight_load_en
    DIRECTION INPUT ;
    USE SIGNAL ;
    ANTENNAGATEAREA 0.929700 ;
    ANTENNADIFFAREA 0.434700 ;
    PORT
      LAYER met3 ;
        RECT 954.040 462.440 958.040 463.040 ;
    END
  END weight_load_en
  OBS
      LAYER li1 ;
        RECT 5.520 10.795 952.200 957.525 ;
      LAYER met1 ;
        RECT 0.070 8.200 956.730 958.760 ;
      LAYER met2 ;
        RECT 0.100 964.480 6.250 965.330 ;
        RECT 7.090 964.480 15.910 965.330 ;
        RECT 16.750 964.480 28.790 965.330 ;
        RECT 29.630 964.480 38.450 965.330 ;
        RECT 39.290 964.480 48.110 965.330 ;
        RECT 48.950 964.480 60.990 965.330 ;
        RECT 61.830 964.480 70.650 965.330 ;
        RECT 71.490 964.480 83.530 965.330 ;
        RECT 84.370 964.480 93.190 965.330 ;
        RECT 94.030 964.480 102.850 965.330 ;
        RECT 103.690 964.480 115.730 965.330 ;
        RECT 116.570 964.480 125.390 965.330 ;
        RECT 126.230 964.480 138.270 965.330 ;
        RECT 139.110 964.480 147.930 965.330 ;
        RECT 148.770 964.480 160.810 965.330 ;
        RECT 161.650 964.480 170.470 965.330 ;
        RECT 171.310 964.480 180.130 965.330 ;
        RECT 180.970 964.480 193.010 965.330 ;
        RECT 193.850 964.480 202.670 965.330 ;
        RECT 203.510 964.480 215.550 965.330 ;
        RECT 216.390 964.480 225.210 965.330 ;
        RECT 226.050 964.480 238.090 965.330 ;
        RECT 238.930 964.480 247.750 965.330 ;
        RECT 248.590 964.480 257.410 965.330 ;
        RECT 258.250 964.480 270.290 965.330 ;
        RECT 271.130 964.480 279.950 965.330 ;
        RECT 280.790 964.480 292.830 965.330 ;
        RECT 293.670 964.480 302.490 965.330 ;
        RECT 303.330 964.480 312.150 965.330 ;
        RECT 312.990 964.480 325.030 965.330 ;
        RECT 325.870 964.480 334.690 965.330 ;
        RECT 335.530 964.480 347.570 965.330 ;
        RECT 348.410 964.480 357.230 965.330 ;
        RECT 358.070 964.480 370.110 965.330 ;
        RECT 370.950 964.480 379.770 965.330 ;
        RECT 380.610 964.480 389.430 965.330 ;
        RECT 390.270 964.480 402.310 965.330 ;
        RECT 403.150 964.480 411.970 965.330 ;
        RECT 412.810 964.480 424.850 965.330 ;
        RECT 425.690 964.480 434.510 965.330 ;
        RECT 435.350 964.480 444.170 965.330 ;
        RECT 445.010 964.480 457.050 965.330 ;
        RECT 457.890 964.480 466.710 965.330 ;
        RECT 467.550 964.480 479.590 965.330 ;
        RECT 480.430 964.480 489.250 965.330 ;
        RECT 490.090 964.480 502.130 965.330 ;
        RECT 502.970 964.480 511.790 965.330 ;
        RECT 512.630 964.480 521.450 965.330 ;
        RECT 522.290 964.480 534.330 965.330 ;
        RECT 535.170 964.480 543.990 965.330 ;
        RECT 544.830 964.480 556.870 965.330 ;
        RECT 557.710 964.480 566.530 965.330 ;
        RECT 567.370 964.480 579.410 965.330 ;
        RECT 580.250 964.480 589.070 965.330 ;
        RECT 589.910 964.480 598.730 965.330 ;
        RECT 599.570 964.480 611.610 965.330 ;
        RECT 612.450 964.480 621.270 965.330 ;
        RECT 622.110 964.480 634.150 965.330 ;
        RECT 634.990 964.480 643.810 965.330 ;
        RECT 644.650 964.480 653.470 965.330 ;
        RECT 654.310 964.480 666.350 965.330 ;
        RECT 667.190 964.480 676.010 965.330 ;
        RECT 676.850 964.480 688.890 965.330 ;
        RECT 689.730 964.480 698.550 965.330 ;
        RECT 699.390 964.480 711.430 965.330 ;
        RECT 712.270 964.480 721.090 965.330 ;
        RECT 721.930 964.480 730.750 965.330 ;
        RECT 731.590 964.480 743.630 965.330 ;
        RECT 744.470 964.480 753.290 965.330 ;
        RECT 754.130 964.480 766.170 965.330 ;
        RECT 767.010 964.480 775.830 965.330 ;
        RECT 776.670 964.480 785.490 965.330 ;
        RECT 786.330 964.480 798.370 965.330 ;
        RECT 799.210 964.480 808.030 965.330 ;
        RECT 808.870 964.480 820.910 965.330 ;
        RECT 821.750 964.480 830.570 965.330 ;
        RECT 831.410 964.480 843.450 965.330 ;
        RECT 844.290 964.480 853.110 965.330 ;
        RECT 853.950 964.480 862.770 965.330 ;
        RECT 863.610 964.480 875.650 965.330 ;
        RECT 876.490 964.480 885.310 965.330 ;
        RECT 886.150 964.480 898.190 965.330 ;
        RECT 899.030 964.480 907.850 965.330 ;
        RECT 908.690 964.480 920.730 965.330 ;
        RECT 921.570 964.480 930.390 965.330 ;
        RECT 931.230 964.480 940.050 965.330 ;
        RECT 940.890 964.480 952.930 965.330 ;
        RECT 953.770 964.480 956.700 965.330 ;
        RECT 0.100 4.280 956.700 964.480 ;
        RECT 0.650 3.670 9.470 4.280 ;
        RECT 10.310 3.670 19.130 4.280 ;
        RECT 19.970 3.670 32.010 4.280 ;
        RECT 32.850 3.670 41.670 4.280 ;
        RECT 42.510 3.670 54.550 4.280 ;
        RECT 55.390 3.670 64.210 4.280 ;
        RECT 65.050 3.670 73.870 4.280 ;
        RECT 74.710 3.670 86.750 4.280 ;
        RECT 87.590 3.670 96.410 4.280 ;
        RECT 97.250 3.670 109.290 4.280 ;
        RECT 110.130 3.670 118.950 4.280 ;
        RECT 119.790 3.670 131.830 4.280 ;
        RECT 132.670 3.670 141.490 4.280 ;
        RECT 142.330 3.670 151.150 4.280 ;
        RECT 151.990 3.670 164.030 4.280 ;
        RECT 164.870 3.670 173.690 4.280 ;
        RECT 174.530 3.670 186.570 4.280 ;
        RECT 187.410 3.670 196.230 4.280 ;
        RECT 197.070 3.670 205.890 4.280 ;
        RECT 206.730 3.670 218.770 4.280 ;
        RECT 219.610 3.670 228.430 4.280 ;
        RECT 229.270 3.670 241.310 4.280 ;
        RECT 242.150 3.670 250.970 4.280 ;
        RECT 251.810 3.670 263.850 4.280 ;
        RECT 264.690 3.670 273.510 4.280 ;
        RECT 274.350 3.670 283.170 4.280 ;
        RECT 284.010 3.670 296.050 4.280 ;
        RECT 296.890 3.670 305.710 4.280 ;
        RECT 306.550 3.670 318.590 4.280 ;
        RECT 319.430 3.670 328.250 4.280 ;
        RECT 329.090 3.670 341.130 4.280 ;
        RECT 341.970 3.670 350.790 4.280 ;
        RECT 351.630 3.670 360.450 4.280 ;
        RECT 361.290 3.670 373.330 4.280 ;
        RECT 374.170 3.670 382.990 4.280 ;
        RECT 383.830 3.670 395.870 4.280 ;
        RECT 396.710 3.670 405.530 4.280 ;
        RECT 406.370 3.670 415.190 4.280 ;
        RECT 416.030 3.670 428.070 4.280 ;
        RECT 428.910 3.670 437.730 4.280 ;
        RECT 438.570 3.670 450.610 4.280 ;
        RECT 451.450 3.670 460.270 4.280 ;
        RECT 461.110 3.670 473.150 4.280 ;
        RECT 473.990 3.670 482.810 4.280 ;
        RECT 483.650 3.670 492.470 4.280 ;
        RECT 493.310 3.670 505.350 4.280 ;
        RECT 506.190 3.670 515.010 4.280 ;
        RECT 515.850 3.670 527.890 4.280 ;
        RECT 528.730 3.670 537.550 4.280 ;
        RECT 538.390 3.670 547.210 4.280 ;
        RECT 548.050 3.670 560.090 4.280 ;
        RECT 560.930 3.670 569.750 4.280 ;
        RECT 570.590 3.670 582.630 4.280 ;
        RECT 583.470 3.670 592.290 4.280 ;
        RECT 593.130 3.670 605.170 4.280 ;
        RECT 606.010 3.670 614.830 4.280 ;
        RECT 615.670 3.670 624.490 4.280 ;
        RECT 625.330 3.670 637.370 4.280 ;
        RECT 638.210 3.670 647.030 4.280 ;
        RECT 647.870 3.670 659.910 4.280 ;
        RECT 660.750 3.670 669.570 4.280 ;
        RECT 670.410 3.670 682.450 4.280 ;
        RECT 683.290 3.670 692.110 4.280 ;
        RECT 692.950 3.670 701.770 4.280 ;
        RECT 702.610 3.670 714.650 4.280 ;
        RECT 715.490 3.670 724.310 4.280 ;
        RECT 725.150 3.670 737.190 4.280 ;
        RECT 738.030 3.670 746.850 4.280 ;
        RECT 747.690 3.670 756.510 4.280 ;
        RECT 757.350 3.670 769.390 4.280 ;
        RECT 770.230 3.670 779.050 4.280 ;
        RECT 779.890 3.670 791.930 4.280 ;
        RECT 792.770 3.670 801.590 4.280 ;
        RECT 802.430 3.670 814.470 4.280 ;
        RECT 815.310 3.670 824.130 4.280 ;
        RECT 824.970 3.670 833.790 4.280 ;
        RECT 834.630 3.670 846.670 4.280 ;
        RECT 847.510 3.670 856.330 4.280 ;
        RECT 857.170 3.670 869.210 4.280 ;
        RECT 870.050 3.670 878.870 4.280 ;
        RECT 879.710 3.670 888.530 4.280 ;
        RECT 889.370 3.670 901.410 4.280 ;
        RECT 902.250 3.670 911.070 4.280 ;
        RECT 911.910 3.670 923.950 4.280 ;
        RECT 924.790 3.670 933.610 4.280 ;
        RECT 934.450 3.670 946.490 4.280 ;
        RECT 947.330 3.670 956.150 4.280 ;
      LAYER met3 ;
        RECT 4.400 961.840 953.640 962.705 ;
        RECT 3.990 953.040 956.275 961.840 ;
        RECT 4.400 951.640 956.275 953.040 ;
        RECT 3.990 949.640 956.275 951.640 ;
        RECT 3.990 948.240 953.640 949.640 ;
        RECT 3.990 939.440 956.275 948.240 ;
        RECT 4.400 938.040 953.640 939.440 ;
        RECT 3.990 929.240 956.275 938.040 ;
        RECT 4.400 927.840 953.640 929.240 ;
        RECT 3.990 919.040 956.275 927.840 ;
        RECT 4.400 917.640 956.275 919.040 ;
        RECT 3.990 915.640 956.275 917.640 ;
        RECT 3.990 914.240 953.640 915.640 ;
        RECT 3.990 905.440 956.275 914.240 ;
        RECT 4.400 904.040 953.640 905.440 ;
        RECT 3.990 895.240 956.275 904.040 ;
        RECT 4.400 893.840 956.275 895.240 ;
        RECT 3.990 891.840 956.275 893.840 ;
        RECT 3.990 890.440 953.640 891.840 ;
        RECT 3.990 881.640 956.275 890.440 ;
        RECT 4.400 880.240 953.640 881.640 ;
        RECT 3.990 871.440 956.275 880.240 ;
        RECT 4.400 870.040 956.275 871.440 ;
        RECT 3.990 868.040 956.275 870.040 ;
        RECT 3.990 866.640 953.640 868.040 ;
        RECT 3.990 861.240 956.275 866.640 ;
        RECT 4.400 859.840 956.275 861.240 ;
        RECT 3.990 857.840 956.275 859.840 ;
        RECT 3.990 856.440 953.640 857.840 ;
        RECT 3.990 847.640 956.275 856.440 ;
        RECT 4.400 846.240 953.640 847.640 ;
        RECT 3.990 837.440 956.275 846.240 ;
        RECT 4.400 836.040 956.275 837.440 ;
        RECT 3.990 834.040 956.275 836.040 ;
        RECT 3.990 832.640 953.640 834.040 ;
        RECT 3.990 823.840 956.275 832.640 ;
        RECT 4.400 822.440 953.640 823.840 ;
        RECT 3.990 813.640 956.275 822.440 ;
        RECT 4.400 812.240 956.275 813.640 ;
        RECT 3.990 810.240 956.275 812.240 ;
        RECT 3.990 808.840 953.640 810.240 ;
        RECT 3.990 800.040 956.275 808.840 ;
        RECT 4.400 798.640 953.640 800.040 ;
        RECT 3.990 789.840 956.275 798.640 ;
        RECT 4.400 788.440 953.640 789.840 ;
        RECT 3.990 779.640 956.275 788.440 ;
        RECT 4.400 778.240 956.275 779.640 ;
        RECT 3.990 776.240 956.275 778.240 ;
        RECT 3.990 774.840 953.640 776.240 ;
        RECT 3.990 766.040 956.275 774.840 ;
        RECT 4.400 764.640 953.640 766.040 ;
        RECT 3.990 755.840 956.275 764.640 ;
        RECT 4.400 754.440 956.275 755.840 ;
        RECT 3.990 752.440 956.275 754.440 ;
        RECT 3.990 751.040 953.640 752.440 ;
        RECT 3.990 742.240 956.275 751.040 ;
        RECT 4.400 740.840 953.640 742.240 ;
        RECT 3.990 732.040 956.275 740.840 ;
        RECT 4.400 730.640 956.275 732.040 ;
        RECT 3.990 728.640 956.275 730.640 ;
        RECT 3.990 727.240 953.640 728.640 ;
        RECT 3.990 718.440 956.275 727.240 ;
        RECT 4.400 717.040 953.640 718.440 ;
        RECT 3.990 708.240 956.275 717.040 ;
        RECT 4.400 706.840 953.640 708.240 ;
        RECT 3.990 698.040 956.275 706.840 ;
        RECT 4.400 696.640 956.275 698.040 ;
        RECT 3.990 694.640 956.275 696.640 ;
        RECT 3.990 693.240 953.640 694.640 ;
        RECT 3.990 684.440 956.275 693.240 ;
        RECT 4.400 683.040 953.640 684.440 ;
        RECT 3.990 674.240 956.275 683.040 ;
        RECT 4.400 672.840 956.275 674.240 ;
        RECT 3.990 670.840 956.275 672.840 ;
        RECT 3.990 669.440 953.640 670.840 ;
        RECT 3.990 660.640 956.275 669.440 ;
        RECT 4.400 659.240 953.640 660.640 ;
        RECT 3.990 650.440 956.275 659.240 ;
        RECT 4.400 649.040 956.275 650.440 ;
        RECT 3.990 647.040 956.275 649.040 ;
        RECT 3.990 645.640 953.640 647.040 ;
        RECT 3.990 640.240 956.275 645.640 ;
        RECT 4.400 638.840 956.275 640.240 ;
        RECT 3.990 636.840 956.275 638.840 ;
        RECT 3.990 635.440 953.640 636.840 ;
        RECT 3.990 626.640 956.275 635.440 ;
        RECT 4.400 625.240 953.640 626.640 ;
        RECT 3.990 616.440 956.275 625.240 ;
        RECT 4.400 615.040 956.275 616.440 ;
        RECT 3.990 613.040 956.275 615.040 ;
        RECT 3.990 611.640 953.640 613.040 ;
        RECT 3.990 602.840 956.275 611.640 ;
        RECT 4.400 601.440 953.640 602.840 ;
        RECT 3.990 592.640 956.275 601.440 ;
        RECT 4.400 591.240 956.275 592.640 ;
        RECT 3.990 589.240 956.275 591.240 ;
        RECT 3.990 587.840 953.640 589.240 ;
        RECT 3.990 579.040 956.275 587.840 ;
        RECT 4.400 577.640 953.640 579.040 ;
        RECT 3.990 568.840 956.275 577.640 ;
        RECT 4.400 567.440 953.640 568.840 ;
        RECT 3.990 558.640 956.275 567.440 ;
        RECT 4.400 557.240 956.275 558.640 ;
        RECT 3.990 555.240 956.275 557.240 ;
        RECT 3.990 553.840 953.640 555.240 ;
        RECT 3.990 545.040 956.275 553.840 ;
        RECT 4.400 543.640 953.640 545.040 ;
        RECT 3.990 534.840 956.275 543.640 ;
        RECT 4.400 533.440 956.275 534.840 ;
        RECT 3.990 531.440 956.275 533.440 ;
        RECT 3.990 530.040 953.640 531.440 ;
        RECT 3.990 521.240 956.275 530.040 ;
        RECT 4.400 519.840 953.640 521.240 ;
        RECT 3.990 511.040 956.275 519.840 ;
        RECT 4.400 509.640 956.275 511.040 ;
        RECT 3.990 507.640 956.275 509.640 ;
        RECT 3.990 506.240 953.640 507.640 ;
        RECT 3.990 500.840 956.275 506.240 ;
        RECT 4.400 499.440 956.275 500.840 ;
        RECT 3.990 497.440 956.275 499.440 ;
        RECT 3.990 496.040 953.640 497.440 ;
        RECT 3.990 487.240 956.275 496.040 ;
        RECT 4.400 485.840 953.640 487.240 ;
        RECT 3.990 477.040 956.275 485.840 ;
        RECT 4.400 475.640 956.275 477.040 ;
        RECT 3.990 473.640 956.275 475.640 ;
        RECT 3.990 472.240 953.640 473.640 ;
        RECT 3.990 463.440 956.275 472.240 ;
        RECT 4.400 462.040 953.640 463.440 ;
        RECT 3.990 453.240 956.275 462.040 ;
        RECT 4.400 451.840 956.275 453.240 ;
        RECT 3.990 449.840 956.275 451.840 ;
        RECT 3.990 448.440 953.640 449.840 ;
        RECT 3.990 439.640 956.275 448.440 ;
        RECT 4.400 438.240 953.640 439.640 ;
        RECT 3.990 429.440 956.275 438.240 ;
        RECT 4.400 428.040 953.640 429.440 ;
        RECT 3.990 419.240 956.275 428.040 ;
        RECT 4.400 417.840 956.275 419.240 ;
        RECT 3.990 415.840 956.275 417.840 ;
        RECT 3.990 414.440 953.640 415.840 ;
        RECT 3.990 405.640 956.275 414.440 ;
        RECT 4.400 404.240 953.640 405.640 ;
        RECT 3.990 395.440 956.275 404.240 ;
        RECT 4.400 394.040 956.275 395.440 ;
        RECT 3.990 392.040 956.275 394.040 ;
        RECT 3.990 390.640 953.640 392.040 ;
        RECT 3.990 381.840 956.275 390.640 ;
        RECT 4.400 380.440 953.640 381.840 ;
        RECT 3.990 371.640 956.275 380.440 ;
        RECT 4.400 370.240 956.275 371.640 ;
        RECT 3.990 368.240 956.275 370.240 ;
        RECT 3.990 366.840 953.640 368.240 ;
        RECT 3.990 358.040 956.275 366.840 ;
        RECT 4.400 356.640 953.640 358.040 ;
        RECT 3.990 347.840 956.275 356.640 ;
        RECT 4.400 346.440 953.640 347.840 ;
        RECT 3.990 337.640 956.275 346.440 ;
        RECT 4.400 336.240 956.275 337.640 ;
        RECT 3.990 334.240 956.275 336.240 ;
        RECT 3.990 332.840 953.640 334.240 ;
        RECT 3.990 324.040 956.275 332.840 ;
        RECT 4.400 322.640 953.640 324.040 ;
        RECT 3.990 313.840 956.275 322.640 ;
        RECT 4.400 312.440 956.275 313.840 ;
        RECT 3.990 310.440 956.275 312.440 ;
        RECT 3.990 309.040 953.640 310.440 ;
        RECT 3.990 300.240 956.275 309.040 ;
        RECT 4.400 298.840 953.640 300.240 ;
        RECT 3.990 290.040 956.275 298.840 ;
        RECT 4.400 288.640 956.275 290.040 ;
        RECT 3.990 286.640 956.275 288.640 ;
        RECT 3.990 285.240 953.640 286.640 ;
        RECT 3.990 279.840 956.275 285.240 ;
        RECT 4.400 278.440 956.275 279.840 ;
        RECT 3.990 276.440 956.275 278.440 ;
        RECT 3.990 275.040 953.640 276.440 ;
        RECT 3.990 266.240 956.275 275.040 ;
        RECT 4.400 264.840 953.640 266.240 ;
        RECT 3.990 256.040 956.275 264.840 ;
        RECT 4.400 254.640 956.275 256.040 ;
        RECT 3.990 252.640 956.275 254.640 ;
        RECT 3.990 251.240 953.640 252.640 ;
        RECT 3.990 242.440 956.275 251.240 ;
        RECT 4.400 241.040 953.640 242.440 ;
        RECT 3.990 232.240 956.275 241.040 ;
        RECT 4.400 230.840 956.275 232.240 ;
        RECT 3.990 228.840 956.275 230.840 ;
        RECT 3.990 227.440 953.640 228.840 ;
        RECT 3.990 218.640 956.275 227.440 ;
        RECT 4.400 217.240 953.640 218.640 ;
        RECT 3.990 208.440 956.275 217.240 ;
        RECT 4.400 207.040 953.640 208.440 ;
        RECT 3.990 198.240 956.275 207.040 ;
        RECT 4.400 196.840 956.275 198.240 ;
        RECT 3.990 194.840 956.275 196.840 ;
        RECT 3.990 193.440 953.640 194.840 ;
        RECT 3.990 184.640 956.275 193.440 ;
        RECT 4.400 183.240 953.640 184.640 ;
        RECT 3.990 174.440 956.275 183.240 ;
        RECT 4.400 173.040 956.275 174.440 ;
        RECT 3.990 171.040 956.275 173.040 ;
        RECT 3.990 169.640 953.640 171.040 ;
        RECT 3.990 160.840 956.275 169.640 ;
        RECT 4.400 159.440 953.640 160.840 ;
        RECT 3.990 150.640 956.275 159.440 ;
        RECT 4.400 149.240 956.275 150.640 ;
        RECT 3.990 147.240 956.275 149.240 ;
        RECT 3.990 145.840 953.640 147.240 ;
        RECT 3.990 140.440 956.275 145.840 ;
        RECT 4.400 139.040 956.275 140.440 ;
        RECT 3.990 137.040 956.275 139.040 ;
        RECT 3.990 135.640 953.640 137.040 ;
        RECT 3.990 126.840 956.275 135.640 ;
        RECT 4.400 125.440 953.640 126.840 ;
        RECT 3.990 116.640 956.275 125.440 ;
        RECT 4.400 115.240 956.275 116.640 ;
        RECT 3.990 113.240 956.275 115.240 ;
        RECT 3.990 111.840 953.640 113.240 ;
        RECT 3.990 103.040 956.275 111.840 ;
        RECT 4.400 101.640 953.640 103.040 ;
        RECT 3.990 92.840 956.275 101.640 ;
        RECT 4.400 91.440 956.275 92.840 ;
        RECT 3.990 89.440 956.275 91.440 ;
        RECT 3.990 88.040 953.640 89.440 ;
        RECT 3.990 79.240 956.275 88.040 ;
        RECT 4.400 77.840 953.640 79.240 ;
        RECT 3.990 69.040 956.275 77.840 ;
        RECT 4.400 67.640 953.640 69.040 ;
        RECT 3.990 58.840 956.275 67.640 ;
        RECT 4.400 57.440 956.275 58.840 ;
        RECT 3.990 55.440 956.275 57.440 ;
        RECT 3.990 54.040 953.640 55.440 ;
        RECT 3.990 45.240 956.275 54.040 ;
        RECT 4.400 43.840 953.640 45.240 ;
        RECT 3.990 35.040 956.275 43.840 ;
        RECT 4.400 33.640 956.275 35.040 ;
        RECT 3.990 31.640 956.275 33.640 ;
        RECT 3.990 30.240 953.640 31.640 ;
        RECT 3.990 21.440 956.275 30.240 ;
        RECT 4.400 20.040 953.640 21.440 ;
        RECT 3.990 11.240 956.275 20.040 ;
        RECT 4.400 9.840 956.275 11.240 ;
        RECT 3.990 7.840 956.275 9.840 ;
        RECT 3.990 6.975 953.640 7.840 ;
      LAYER met4 ;
        RECT 10.415 11.055 20.640 954.545 ;
        RECT 23.040 11.055 97.440 954.545 ;
        RECT 99.840 11.055 174.240 954.545 ;
        RECT 176.640 11.055 251.040 954.545 ;
        RECT 253.440 11.055 327.840 954.545 ;
        RECT 330.240 11.055 404.640 954.545 ;
        RECT 407.040 11.055 481.440 954.545 ;
        RECT 483.840 11.055 558.240 954.545 ;
        RECT 560.640 11.055 635.040 954.545 ;
        RECT 637.440 11.055 711.840 954.545 ;
        RECT 714.240 11.055 788.640 954.545 ;
        RECT 791.040 11.055 865.440 954.545 ;
        RECT 867.840 11.055 940.865 954.545 ;
  END
END systolic_mm_accel
END LIBRARY

